VERSION 5.7 ;
BUSBITCHARS "[]" ;
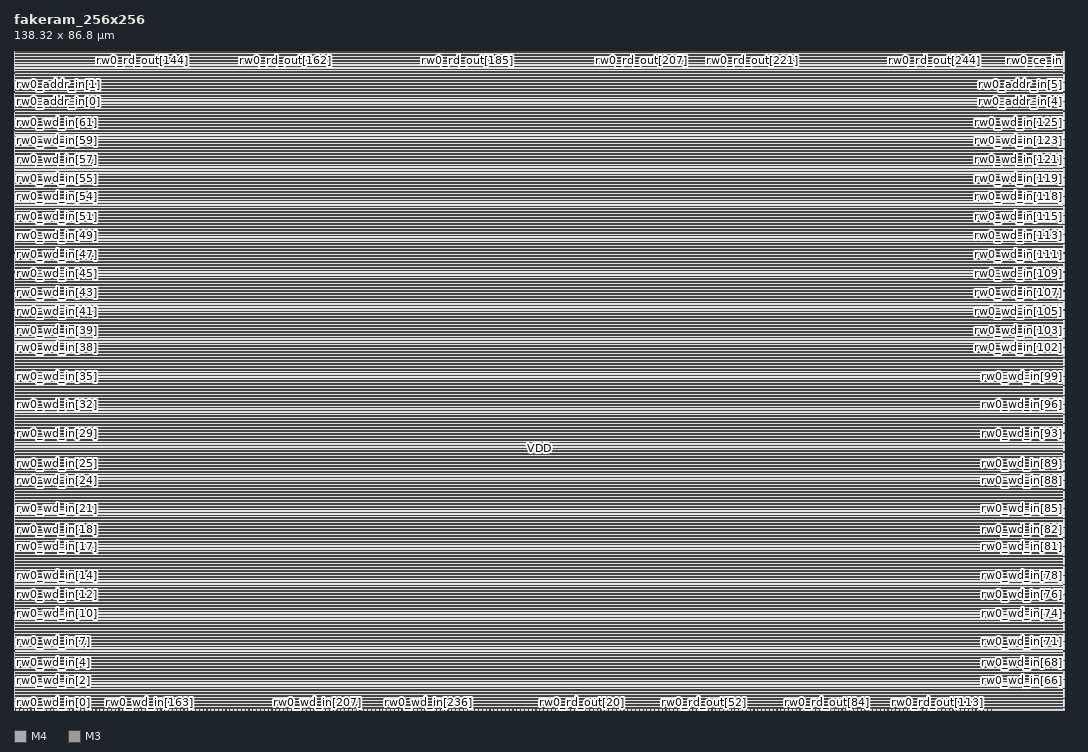
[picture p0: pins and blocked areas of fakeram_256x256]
MACRO fakeram_256x256
  FOREIGN fakeram_256x256 0 0 ;
  SYMMETRY X Y R90 ;
  SIZE 138.320 BY 86.800 ;
  CLASS BLOCK ;
  PIN rw0_wd_in[0]
    DIRECTION INPUT ;
    USE SIGNAL ;
    SHAPE ABUTMENT ;
    PORT
      LAYER M4 ;
      RECT 0.000 0.276 0.072 0.300 ;
    END
  END rw0_wd_in[0]
  PIN rw0_wd_in[1]
    DIRECTION INPUT ;
    USE SIGNAL ;
    SHAPE ABUTMENT ;
    PORT
      LAYER M4 ;
      RECT 0.000 1.524 0.072 1.548 ;
    END
  END rw0_wd_in[1]
  PIN rw0_wd_in[2]
    DIRECTION INPUT ;
    USE SIGNAL ;
    SHAPE ABUTMENT ;
    PORT
      LAYER M4 ;
      RECT 0.000 2.772 0.072 2.796 ;
    END
  END rw0_wd_in[2]
  PIN rw0_wd_in[3]
    DIRECTION INPUT ;
    USE SIGNAL ;
    SHAPE ABUTMENT ;
    PORT
      LAYER M4 ;
      RECT 0.000 4.020 0.072 4.044 ;
    END
  END rw0_wd_in[3]
  PIN rw0_wd_in[4]
    DIRECTION INPUT ;
    USE SIGNAL ;
    SHAPE ABUTMENT ;
    PORT
      LAYER M4 ;
      RECT 0.000 5.268 0.072 5.292 ;
    END
  END rw0_wd_in[4]
  PIN rw0_wd_in[5]
    DIRECTION INPUT ;
    USE SIGNAL ;
    SHAPE ABUTMENT ;
    PORT
      LAYER M4 ;
      RECT 0.000 6.516 0.072 6.540 ;
    END
  END rw0_wd_in[5]
  PIN rw0_wd_in[6]
    DIRECTION INPUT ;
    USE SIGNAL ;
    SHAPE ABUTMENT ;
    PORT
      LAYER M4 ;
      RECT 0.000 7.764 0.072 7.788 ;
    END
  END rw0_wd_in[6]
  PIN rw0_wd_in[7]
    DIRECTION INPUT ;
    USE SIGNAL ;
    SHAPE ABUTMENT ;
    PORT
      LAYER M4 ;
      RECT 0.000 9.012 0.072 9.036 ;
    END
  END rw0_wd_in[7]
  PIN rw0_wd_in[8]
    DIRECTION INPUT ;
    USE SIGNAL ;
    SHAPE ABUTMENT ;
    PORT
      LAYER M4 ;
      RECT 0.000 10.260 0.072 10.284 ;
    END
  END rw0_wd_in[8]
  PIN rw0_wd_in[9]
    DIRECTION INPUT ;
    USE SIGNAL ;
    SHAPE ABUTMENT ;
    PORT
      LAYER M4 ;
      RECT 0.000 11.508 0.072 11.532 ;
    END
  END rw0_wd_in[9]
  PIN rw0_wd_in[10]
    DIRECTION INPUT ;
    USE SIGNAL ;
    SHAPE ABUTMENT ;
    PORT
      LAYER M4 ;
      RECT 0.000 12.756 0.072 12.780 ;
    END
  END rw0_wd_in[10]
  PIN rw0_wd_in[11]
    DIRECTION INPUT ;
    USE SIGNAL ;
    SHAPE ABUTMENT ;
    PORT
      LAYER M4 ;
      RECT 0.000 14.004 0.072 14.028 ;
    END
  END rw0_wd_in[11]
  PIN rw0_wd_in[12]
    DIRECTION INPUT ;
    USE SIGNAL ;
    SHAPE ABUTMENT ;
    PORT
      LAYER M4 ;
      RECT 0.000 15.252 0.072 15.276 ;
    END
  END rw0_wd_in[12]
  PIN rw0_wd_in[13]
    DIRECTION INPUT ;
    USE SIGNAL ;
    SHAPE ABUTMENT ;
    PORT
      LAYER M4 ;
      RECT 0.000 16.500 0.072 16.524 ;
    END
  END rw0_wd_in[13]
  PIN rw0_wd_in[14]
    DIRECTION INPUT ;
    USE SIGNAL ;
    SHAPE ABUTMENT ;
    PORT
      LAYER M4 ;
      RECT 0.000 17.748 0.072 17.772 ;
    END
  END rw0_wd_in[14]
  PIN rw0_wd_in[15]
    DIRECTION INPUT ;
    USE SIGNAL ;
    SHAPE ABUTMENT ;
    PORT
      LAYER M4 ;
      RECT 0.000 18.996 0.072 19.020 ;
    END
  END rw0_wd_in[15]
  PIN rw0_wd_in[16]
    DIRECTION INPUT ;
    USE SIGNAL ;
    SHAPE ABUTMENT ;
    PORT
      LAYER M4 ;
      RECT 0.000 20.244 0.072 20.268 ;
    END
  END rw0_wd_in[16]
  PIN rw0_wd_in[17]
    DIRECTION INPUT ;
    USE SIGNAL ;
    SHAPE ABUTMENT ;
    PORT
      LAYER M4 ;
      RECT 0.000 21.492 0.072 21.516 ;
    END
  END rw0_wd_in[17]
  PIN rw0_wd_in[18]
    DIRECTION INPUT ;
    USE SIGNAL ;
    SHAPE ABUTMENT ;
    PORT
      LAYER M4 ;
      RECT 0.000 22.740 0.072 22.764 ;
    END
  END rw0_wd_in[18]
  PIN rw0_wd_in[19]
    DIRECTION INPUT ;
    USE SIGNAL ;
    SHAPE ABUTMENT ;
    PORT
      LAYER M4 ;
      RECT 0.000 23.988 0.072 24.012 ;
    END
  END rw0_wd_in[19]
  PIN rw0_wd_in[20]
    DIRECTION INPUT ;
    USE SIGNAL ;
    SHAPE ABUTMENT ;
    PORT
      LAYER M4 ;
      RECT 0.000 25.236 0.072 25.260 ;
    END
  END rw0_wd_in[20]
  PIN rw0_wd_in[21]
    DIRECTION INPUT ;
    USE SIGNAL ;
    SHAPE ABUTMENT ;
    PORT
      LAYER M4 ;
      RECT 0.000 26.484 0.072 26.508 ;
    END
  END rw0_wd_in[21]
  PIN rw0_wd_in[22]
    DIRECTION INPUT ;
    USE SIGNAL ;
    SHAPE ABUTMENT ;
    PORT
      LAYER M4 ;
      RECT 0.000 27.732 0.072 27.756 ;
    END
  END rw0_wd_in[22]
  PIN rw0_wd_in[23]
    DIRECTION INPUT ;
    USE SIGNAL ;
    SHAPE ABUTMENT ;
    PORT
      LAYER M4 ;
      RECT 0.000 28.980 0.072 29.004 ;
    END
  END rw0_wd_in[23]
  PIN rw0_wd_in[24]
    DIRECTION INPUT ;
    USE SIGNAL ;
    SHAPE ABUTMENT ;
    PORT
      LAYER M4 ;
      RECT 0.000 30.228 0.072 30.252 ;
    END
  END rw0_wd_in[24]
  PIN rw0_wd_in[25]
    DIRECTION INPUT ;
    USE SIGNAL ;
    SHAPE ABUTMENT ;
    PORT
      LAYER M4 ;
      RECT 0.000 31.476 0.072 31.500 ;
    END
  END rw0_wd_in[25]
  PIN rw0_wd_in[26]
    DIRECTION INPUT ;
    USE SIGNAL ;
    SHAPE ABUTMENT ;
    PORT
      LAYER M4 ;
      RECT 0.000 32.724 0.072 32.748 ;
    END
  END rw0_wd_in[26]
  PIN rw0_wd_in[27]
    DIRECTION INPUT ;
    USE SIGNAL ;
    SHAPE ABUTMENT ;
    PORT
      LAYER M4 ;
      RECT 0.000 33.972 0.072 33.996 ;
    END
  END rw0_wd_in[27]
  PIN rw0_wd_in[28]
    DIRECTION INPUT ;
    USE SIGNAL ;
    SHAPE ABUTMENT ;
    PORT
      LAYER M4 ;
      RECT 0.000 35.220 0.072 35.244 ;
    END
  END rw0_wd_in[28]
  PIN rw0_wd_in[29]
    DIRECTION INPUT ;
    USE SIGNAL ;
    SHAPE ABUTMENT ;
    PORT
      LAYER M4 ;
      RECT 0.000 36.468 0.072 36.492 ;
    END
  END rw0_wd_in[29]
  PIN rw0_wd_in[30]
    DIRECTION INPUT ;
    USE SIGNAL ;
    SHAPE ABUTMENT ;
    PORT
      LAYER M4 ;
      RECT 0.000 37.716 0.072 37.740 ;
    END
  END rw0_wd_in[30]
  PIN rw0_wd_in[31]
    DIRECTION INPUT ;
    USE SIGNAL ;
    SHAPE ABUTMENT ;
    PORT
      LAYER M4 ;
      RECT 0.000 38.964 0.072 38.988 ;
    END
  END rw0_wd_in[31]
  PIN rw0_wd_in[32]
    DIRECTION INPUT ;
    USE SIGNAL ;
    SHAPE ABUTMENT ;
    PORT
      LAYER M4 ;
      RECT 0.000 40.212 0.072 40.236 ;
    END
  END rw0_wd_in[32]
  PIN rw0_wd_in[33]
    DIRECTION INPUT ;
    USE SIGNAL ;
    SHAPE ABUTMENT ;
    PORT
      LAYER M4 ;
      RECT 0.000 41.460 0.072 41.484 ;
    END
  END rw0_wd_in[33]
  PIN rw0_wd_in[34]
    DIRECTION INPUT ;
    USE SIGNAL ;
    SHAPE ABUTMENT ;
    PORT
      LAYER M4 ;
      RECT 0.000 42.708 0.072 42.732 ;
    END
  END rw0_wd_in[34]
  PIN rw0_wd_in[35]
    DIRECTION INPUT ;
    USE SIGNAL ;
    SHAPE ABUTMENT ;
    PORT
      LAYER M4 ;
      RECT 0.000 43.956 0.072 43.980 ;
    END
  END rw0_wd_in[35]
  PIN rw0_wd_in[36]
    DIRECTION INPUT ;
    USE SIGNAL ;
    SHAPE ABUTMENT ;
    PORT
      LAYER M4 ;
      RECT 0.000 45.204 0.072 45.228 ;
    END
  END rw0_wd_in[36]
  PIN rw0_wd_in[37]
    DIRECTION INPUT ;
    USE SIGNAL ;
    SHAPE ABUTMENT ;
    PORT
      LAYER M4 ;
      RECT 0.000 46.452 0.072 46.476 ;
    END
  END rw0_wd_in[37]
  PIN rw0_wd_in[38]
    DIRECTION INPUT ;
    USE SIGNAL ;
    SHAPE ABUTMENT ;
    PORT
      LAYER M4 ;
      RECT 0.000 47.700 0.072 47.724 ;
    END
  END rw0_wd_in[38]
  PIN rw0_wd_in[39]
    DIRECTION INPUT ;
    USE SIGNAL ;
    SHAPE ABUTMENT ;
    PORT
      LAYER M4 ;
      RECT 0.000 48.948 0.072 48.972 ;
    END
  END rw0_wd_in[39]
  PIN rw0_wd_in[40]
    DIRECTION INPUT ;
    USE SIGNAL ;
    SHAPE ABUTMENT ;
    PORT
      LAYER M4 ;
      RECT 0.000 50.196 0.072 50.220 ;
    END
  END rw0_wd_in[40]
  PIN rw0_wd_in[41]
    DIRECTION INPUT ;
    USE SIGNAL ;
    SHAPE ABUTMENT ;
    PORT
      LAYER M4 ;
      RECT 0.000 51.444 0.072 51.468 ;
    END
  END rw0_wd_in[41]
  PIN rw0_wd_in[42]
    DIRECTION INPUT ;
    USE SIGNAL ;
    SHAPE ABUTMENT ;
    PORT
      LAYER M4 ;
      RECT 0.000 52.692 0.072 52.716 ;
    END
  END rw0_wd_in[42]
  PIN rw0_wd_in[43]
    DIRECTION INPUT ;
    USE SIGNAL ;
    SHAPE ABUTMENT ;
    PORT
      LAYER M4 ;
      RECT 0.000 53.940 0.072 53.964 ;
    END
  END rw0_wd_in[43]
  PIN rw0_wd_in[44]
    DIRECTION INPUT ;
    USE SIGNAL ;
    SHAPE ABUTMENT ;
    PORT
      LAYER M4 ;
      RECT 0.000 55.188 0.072 55.212 ;
    END
  END rw0_wd_in[44]
  PIN rw0_wd_in[45]
    DIRECTION INPUT ;
    USE SIGNAL ;
    SHAPE ABUTMENT ;
    PORT
      LAYER M4 ;
      RECT 0.000 56.436 0.072 56.460 ;
    END
  END rw0_wd_in[45]
  PIN rw0_wd_in[46]
    DIRECTION INPUT ;
    USE SIGNAL ;
    SHAPE ABUTMENT ;
    PORT
      LAYER M4 ;
      RECT 0.000 57.684 0.072 57.708 ;
    END
  END rw0_wd_in[46]
  PIN rw0_wd_in[47]
    DIRECTION INPUT ;
    USE SIGNAL ;
    SHAPE ABUTMENT ;
    PORT
      LAYER M4 ;
      RECT 0.000 58.932 0.072 58.956 ;
    END
  END rw0_wd_in[47]
  PIN rw0_wd_in[48]
    DIRECTION INPUT ;
    USE SIGNAL ;
    SHAPE ABUTMENT ;
    PORT
      LAYER M4 ;
      RECT 0.000 60.180 0.072 60.204 ;
    END
  END rw0_wd_in[48]
  PIN rw0_wd_in[49]
    DIRECTION INPUT ;
    USE SIGNAL ;
    SHAPE ABUTMENT ;
    PORT
      LAYER M4 ;
      RECT 0.000 61.428 0.072 61.452 ;
    END
  END rw0_wd_in[49]
  PIN rw0_wd_in[50]
    DIRECTION INPUT ;
    USE SIGNAL ;
    SHAPE ABUTMENT ;
    PORT
      LAYER M4 ;
      RECT 0.000 62.676 0.072 62.700 ;
    END
  END rw0_wd_in[50]
  PIN rw0_wd_in[51]
    DIRECTION INPUT ;
    USE SIGNAL ;
    SHAPE ABUTMENT ;
    PORT
      LAYER M4 ;
      RECT 0.000 63.924 0.072 63.948 ;
    END
  END rw0_wd_in[51]
  PIN rw0_wd_in[52]
    DIRECTION INPUT ;
    USE SIGNAL ;
    SHAPE ABUTMENT ;
    PORT
      LAYER M4 ;
      RECT 0.000 65.172 0.072 65.196 ;
    END
  END rw0_wd_in[52]
  PIN rw0_wd_in[53]
    DIRECTION INPUT ;
    USE SIGNAL ;
    SHAPE ABUTMENT ;
    PORT
      LAYER M4 ;
      RECT 0.000 66.420 0.072 66.444 ;
    END
  END rw0_wd_in[53]
  PIN rw0_wd_in[54]
    DIRECTION INPUT ;
    USE SIGNAL ;
    SHAPE ABUTMENT ;
    PORT
      LAYER M4 ;
      RECT 0.000 67.668 0.072 67.692 ;
    END
  END rw0_wd_in[54]
  PIN rw0_wd_in[55]
    DIRECTION INPUT ;
    USE SIGNAL ;
    SHAPE ABUTMENT ;
    PORT
      LAYER M4 ;
      RECT 0.000 68.916 0.072 68.940 ;
    END
  END rw0_wd_in[55]
  PIN rw0_wd_in[56]
    DIRECTION INPUT ;
    USE SIGNAL ;
    SHAPE ABUTMENT ;
    PORT
      LAYER M4 ;
      RECT 0.000 70.164 0.072 70.188 ;
    END
  END rw0_wd_in[56]
  PIN rw0_wd_in[57]
    DIRECTION INPUT ;
    USE SIGNAL ;
    SHAPE ABUTMENT ;
    PORT
      LAYER M4 ;
      RECT 0.000 71.412 0.072 71.436 ;
    END
  END rw0_wd_in[57]
  PIN rw0_wd_in[58]
    DIRECTION INPUT ;
    USE SIGNAL ;
    SHAPE ABUTMENT ;
    PORT
      LAYER M4 ;
      RECT 0.000 72.660 0.072 72.684 ;
    END
  END rw0_wd_in[58]
  PIN rw0_wd_in[59]
    DIRECTION INPUT ;
    USE SIGNAL ;
    SHAPE ABUTMENT ;
    PORT
      LAYER M4 ;
      RECT 0.000 73.908 0.072 73.932 ;
    END
  END rw0_wd_in[59]
  PIN rw0_wd_in[60]
    DIRECTION INPUT ;
    USE SIGNAL ;
    SHAPE ABUTMENT ;
    PORT
      LAYER M4 ;
      RECT 0.000 75.156 0.072 75.180 ;
    END
  END rw0_wd_in[60]
  PIN rw0_wd_in[61]
    DIRECTION INPUT ;
    USE SIGNAL ;
    SHAPE ABUTMENT ;
    PORT
      LAYER M4 ;
      RECT 0.000 76.404 0.072 76.428 ;
    END
  END rw0_wd_in[61]
  PIN rw0_wd_in[62]
    DIRECTION INPUT ;
    USE SIGNAL ;
    SHAPE ABUTMENT ;
    PORT
      LAYER M4 ;
      RECT 0.000 77.652 0.072 77.676 ;
    END
  END rw0_wd_in[62]
  PIN rw0_wd_in[63]
    DIRECTION INPUT ;
    USE SIGNAL ;
    SHAPE ABUTMENT ;
    PORT
      LAYER M4 ;
      RECT 0.000 78.900 0.072 78.924 ;
    END
  END rw0_wd_in[63]
  PIN rw0_wd_in[64]
    DIRECTION INPUT ;
    USE SIGNAL ;
    SHAPE ABUTMENT ;
    PORT
      LAYER M4 ;
      RECT 138.248 0.276 138.320 0.300 ;
    END
  END rw0_wd_in[64]
  PIN rw0_wd_in[65]
    DIRECTION INPUT ;
    USE SIGNAL ;
    SHAPE ABUTMENT ;
    PORT
      LAYER M4 ;
      RECT 138.248 1.524 138.320 1.548 ;
    END
  END rw0_wd_in[65]
  PIN rw0_wd_in[66]
    DIRECTION INPUT ;
    USE SIGNAL ;
    SHAPE ABUTMENT ;
    PORT
      LAYER M4 ;
      RECT 138.248 2.772 138.320 2.796 ;
    END
  END rw0_wd_in[66]
  PIN rw0_wd_in[67]
    DIRECTION INPUT ;
    USE SIGNAL ;
    SHAPE ABUTMENT ;
    PORT
      LAYER M4 ;
      RECT 138.248 4.020 138.320 4.044 ;
    END
  END rw0_wd_in[67]
  PIN rw0_wd_in[68]
    DIRECTION INPUT ;
    USE SIGNAL ;
    SHAPE ABUTMENT ;
    PORT
      LAYER M4 ;
      RECT 138.248 5.268 138.320 5.292 ;
    END
  END rw0_wd_in[68]
  PIN rw0_wd_in[69]
    DIRECTION INPUT ;
    USE SIGNAL ;
    SHAPE ABUTMENT ;
    PORT
      LAYER M4 ;
      RECT 138.248 6.516 138.320 6.540 ;
    END
  END rw0_wd_in[69]
  PIN rw0_wd_in[70]
    DIRECTION INPUT ;
    USE SIGNAL ;
    SHAPE ABUTMENT ;
    PORT
      LAYER M4 ;
      RECT 138.248 7.764 138.320 7.788 ;
    END
  END rw0_wd_in[70]
  PIN rw0_wd_in[71]
    DIRECTION INPUT ;
    USE SIGNAL ;
    SHAPE ABUTMENT ;
    PORT
      LAYER M4 ;
      RECT 138.248 9.012 138.320 9.036 ;
    END
  END rw0_wd_in[71]
  PIN rw0_wd_in[72]
    DIRECTION INPUT ;
    USE SIGNAL ;
    SHAPE ABUTMENT ;
    PORT
      LAYER M4 ;
      RECT 138.248 10.260 138.320 10.284 ;
    END
  END rw0_wd_in[72]
  PIN rw0_wd_in[73]
    DIRECTION INPUT ;
    USE SIGNAL ;
    SHAPE ABUTMENT ;
    PORT
      LAYER M4 ;
      RECT 138.248 11.508 138.320 11.532 ;
    END
  END rw0_wd_in[73]
  PIN rw0_wd_in[74]
    DIRECTION INPUT ;
    USE SIGNAL ;
    SHAPE ABUTMENT ;
    PORT
      LAYER M4 ;
      RECT 138.248 12.756 138.320 12.780 ;
    END
  END rw0_wd_in[74]
  PIN rw0_wd_in[75]
    DIRECTION INPUT ;
    USE SIGNAL ;
    SHAPE ABUTMENT ;
    PORT
      LAYER M4 ;
      RECT 138.248 14.004 138.320 14.028 ;
    END
  END rw0_wd_in[75]
  PIN rw0_wd_in[76]
    DIRECTION INPUT ;
    USE SIGNAL ;
    SHAPE ABUTMENT ;
    PORT
      LAYER M4 ;
      RECT 138.248 15.252 138.320 15.276 ;
    END
  END rw0_wd_in[76]
  PIN rw0_wd_in[77]
    DIRECTION INPUT ;
    USE SIGNAL ;
    SHAPE ABUTMENT ;
    PORT
      LAYER M4 ;
      RECT 138.248 16.500 138.320 16.524 ;
    END
  END rw0_wd_in[77]
  PIN rw0_wd_in[78]
    DIRECTION INPUT ;
    USE SIGNAL ;
    SHAPE ABUTMENT ;
    PORT
      LAYER M4 ;
      RECT 138.248 17.748 138.320 17.772 ;
    END
  END rw0_wd_in[78]
  PIN rw0_wd_in[79]
    DIRECTION INPUT ;
    USE SIGNAL ;
    SHAPE ABUTMENT ;
    PORT
      LAYER M4 ;
      RECT 138.248 18.996 138.320 19.020 ;
    END
  END rw0_wd_in[79]
  PIN rw0_wd_in[80]
    DIRECTION INPUT ;
    USE SIGNAL ;
    SHAPE ABUTMENT ;
    PORT
      LAYER M4 ;
      RECT 138.248 20.244 138.320 20.268 ;
    END
  END rw0_wd_in[80]
  PIN rw0_wd_in[81]
    DIRECTION INPUT ;
    USE SIGNAL ;
    SHAPE ABUTMENT ;
    PORT
      LAYER M4 ;
      RECT 138.248 21.492 138.320 21.516 ;
    END
  END rw0_wd_in[81]
  PIN rw0_wd_in[82]
    DIRECTION INPUT ;
    USE SIGNAL ;
    SHAPE ABUTMENT ;
    PORT
      LAYER M4 ;
      RECT 138.248 22.740 138.320 22.764 ;
    END
  END rw0_wd_in[82]
  PIN rw0_wd_in[83]
    DIRECTION INPUT ;
    USE SIGNAL ;
    SHAPE ABUTMENT ;
    PORT
      LAYER M4 ;
      RECT 138.248 23.988 138.320 24.012 ;
    END
  END rw0_wd_in[83]
  PIN rw0_wd_in[84]
    DIRECTION INPUT ;
    USE SIGNAL ;
    SHAPE ABUTMENT ;
    PORT
      LAYER M4 ;
      RECT 138.248 25.236 138.320 25.260 ;
    END
  END rw0_wd_in[84]
  PIN rw0_wd_in[85]
    DIRECTION INPUT ;
    USE SIGNAL ;
    SHAPE ABUTMENT ;
    PORT
      LAYER M4 ;
      RECT 138.248 26.484 138.320 26.508 ;
    END
  END rw0_wd_in[85]
  PIN rw0_wd_in[86]
    DIRECTION INPUT ;
    USE SIGNAL ;
    SHAPE ABUTMENT ;
    PORT
      LAYER M4 ;
      RECT 138.248 27.732 138.320 27.756 ;
    END
  END rw0_wd_in[86]
  PIN rw0_wd_in[87]
    DIRECTION INPUT ;
    USE SIGNAL ;
    SHAPE ABUTMENT ;
    PORT
      LAYER M4 ;
      RECT 138.248 28.980 138.320 29.004 ;
    END
  END rw0_wd_in[87]
  PIN rw0_wd_in[88]
    DIRECTION INPUT ;
    USE SIGNAL ;
    SHAPE ABUTMENT ;
    PORT
      LAYER M4 ;
      RECT 138.248 30.228 138.320 30.252 ;
    END
  END rw0_wd_in[88]
  PIN rw0_wd_in[89]
    DIRECTION INPUT ;
    USE SIGNAL ;
    SHAPE ABUTMENT ;
    PORT
      LAYER M4 ;
      RECT 138.248 31.476 138.320 31.500 ;
    END
  END rw0_wd_in[89]
  PIN rw0_wd_in[90]
    DIRECTION INPUT ;
    USE SIGNAL ;
    SHAPE ABUTMENT ;
    PORT
      LAYER M4 ;
      RECT 138.248 32.724 138.320 32.748 ;
    END
  END rw0_wd_in[90]
  PIN rw0_wd_in[91]
    DIRECTION INPUT ;
    USE SIGNAL ;
    SHAPE ABUTMENT ;
    PORT
      LAYER M4 ;
      RECT 138.248 33.972 138.320 33.996 ;
    END
  END rw0_wd_in[91]
  PIN rw0_wd_in[92]
    DIRECTION INPUT ;
    USE SIGNAL ;
    SHAPE ABUTMENT ;
    PORT
      LAYER M4 ;
      RECT 138.248 35.220 138.320 35.244 ;
    END
  END rw0_wd_in[92]
  PIN rw0_wd_in[93]
    DIRECTION INPUT ;
    USE SIGNAL ;
    SHAPE ABUTMENT ;
    PORT
      LAYER M4 ;
      RECT 138.248 36.468 138.320 36.492 ;
    END
  END rw0_wd_in[93]
  PIN rw0_wd_in[94]
    DIRECTION INPUT ;
    USE SIGNAL ;
    SHAPE ABUTMENT ;
    PORT
      LAYER M4 ;
      RECT 138.248 37.716 138.320 37.740 ;
    END
  END rw0_wd_in[94]
  PIN rw0_wd_in[95]
    DIRECTION INPUT ;
    USE SIGNAL ;
    SHAPE ABUTMENT ;
    PORT
      LAYER M4 ;
      RECT 138.248 38.964 138.320 38.988 ;
    END
  END rw0_wd_in[95]
  PIN rw0_wd_in[96]
    DIRECTION INPUT ;
    USE SIGNAL ;
    SHAPE ABUTMENT ;
    PORT
      LAYER M4 ;
      RECT 138.248 40.212 138.320 40.236 ;
    END
  END rw0_wd_in[96]
  PIN rw0_wd_in[97]
    DIRECTION INPUT ;
    USE SIGNAL ;
    SHAPE ABUTMENT ;
    PORT
      LAYER M4 ;
      RECT 138.248 41.460 138.320 41.484 ;
    END
  END rw0_wd_in[97]
  PIN rw0_wd_in[98]
    DIRECTION INPUT ;
    USE SIGNAL ;
    SHAPE ABUTMENT ;
    PORT
      LAYER M4 ;
      RECT 138.248 42.708 138.320 42.732 ;
    END
  END rw0_wd_in[98]
  PIN rw0_wd_in[99]
    DIRECTION INPUT ;
    USE SIGNAL ;
    SHAPE ABUTMENT ;
    PORT
      LAYER M4 ;
      RECT 138.248 43.956 138.320 43.980 ;
    END
  END rw0_wd_in[99]
  PIN rw0_wd_in[100]
    DIRECTION INPUT ;
    USE SIGNAL ;
    SHAPE ABUTMENT ;
    PORT
      LAYER M4 ;
      RECT 138.248 45.204 138.320 45.228 ;
    END
  END rw0_wd_in[100]
  PIN rw0_wd_in[101]
    DIRECTION INPUT ;
    USE SIGNAL ;
    SHAPE ABUTMENT ;
    PORT
      LAYER M4 ;
      RECT 138.248 46.452 138.320 46.476 ;
    END
  END rw0_wd_in[101]
  PIN rw0_wd_in[102]
    DIRECTION INPUT ;
    USE SIGNAL ;
    SHAPE ABUTMENT ;
    PORT
      LAYER M4 ;
      RECT 138.248 47.700 138.320 47.724 ;
    END
  END rw0_wd_in[102]
  PIN rw0_wd_in[103]
    DIRECTION INPUT ;
    USE SIGNAL ;
    SHAPE ABUTMENT ;
    PORT
      LAYER M4 ;
      RECT 138.248 48.948 138.320 48.972 ;
    END
  END rw0_wd_in[103]
  PIN rw0_wd_in[104]
    DIRECTION INPUT ;
    USE SIGNAL ;
    SHAPE ABUTMENT ;
    PORT
      LAYER M4 ;
      RECT 138.248 50.196 138.320 50.220 ;
    END
  END rw0_wd_in[104]
  PIN rw0_wd_in[105]
    DIRECTION INPUT ;
    USE SIGNAL ;
    SHAPE ABUTMENT ;
    PORT
      LAYER M4 ;
      RECT 138.248 51.444 138.320 51.468 ;
    END
  END rw0_wd_in[105]
  PIN rw0_wd_in[106]
    DIRECTION INPUT ;
    USE SIGNAL ;
    SHAPE ABUTMENT ;
    PORT
      LAYER M4 ;
      RECT 138.248 52.692 138.320 52.716 ;
    END
  END rw0_wd_in[106]
  PIN rw0_wd_in[107]
    DIRECTION INPUT ;
    USE SIGNAL ;
    SHAPE ABUTMENT ;
    PORT
      LAYER M4 ;
      RECT 138.248 53.940 138.320 53.964 ;
    END
  END rw0_wd_in[107]
  PIN rw0_wd_in[108]
    DIRECTION INPUT ;
    USE SIGNAL ;
    SHAPE ABUTMENT ;
    PORT
      LAYER M4 ;
      RECT 138.248 55.188 138.320 55.212 ;
    END
  END rw0_wd_in[108]
  PIN rw0_wd_in[109]
    DIRECTION INPUT ;
    USE SIGNAL ;
    SHAPE ABUTMENT ;
    PORT
      LAYER M4 ;
      RECT 138.248 56.436 138.320 56.460 ;
    END
  END rw0_wd_in[109]
  PIN rw0_wd_in[110]
    DIRECTION INPUT ;
    USE SIGNAL ;
    SHAPE ABUTMENT ;
    PORT
      LAYER M4 ;
      RECT 138.248 57.684 138.320 57.708 ;
    END
  END rw0_wd_in[110]
  PIN rw0_wd_in[111]
    DIRECTION INPUT ;
    USE SIGNAL ;
    SHAPE ABUTMENT ;
    PORT
      LAYER M4 ;
      RECT 138.248 58.932 138.320 58.956 ;
    END
  END rw0_wd_in[111]
  PIN rw0_wd_in[112]
    DIRECTION INPUT ;
    USE SIGNAL ;
    SHAPE ABUTMENT ;
    PORT
      LAYER M4 ;
      RECT 138.248 60.180 138.320 60.204 ;
    END
  END rw0_wd_in[112]
  PIN rw0_wd_in[113]
    DIRECTION INPUT ;
    USE SIGNAL ;
    SHAPE ABUTMENT ;
    PORT
      LAYER M4 ;
      RECT 138.248 61.428 138.320 61.452 ;
    END
  END rw0_wd_in[113]
  PIN rw0_wd_in[114]
    DIRECTION INPUT ;
    USE SIGNAL ;
    SHAPE ABUTMENT ;
    PORT
      LAYER M4 ;
      RECT 138.248 62.676 138.320 62.700 ;
    END
  END rw0_wd_in[114]
  PIN rw0_wd_in[115]
    DIRECTION INPUT ;
    USE SIGNAL ;
    SHAPE ABUTMENT ;
    PORT
      LAYER M4 ;
      RECT 138.248 63.924 138.320 63.948 ;
    END
  END rw0_wd_in[115]
  PIN rw0_wd_in[116]
    DIRECTION INPUT ;
    USE SIGNAL ;
    SHAPE ABUTMENT ;
    PORT
      LAYER M4 ;
      RECT 138.248 65.172 138.320 65.196 ;
    END
  END rw0_wd_in[116]
  PIN rw0_wd_in[117]
    DIRECTION INPUT ;
    USE SIGNAL ;
    SHAPE ABUTMENT ;
    PORT
      LAYER M4 ;
      RECT 138.248 66.420 138.320 66.444 ;
    END
  END rw0_wd_in[117]
  PIN rw0_wd_in[118]
    DIRECTION INPUT ;
    USE SIGNAL ;
    SHAPE ABUTMENT ;
    PORT
      LAYER M4 ;
      RECT 138.248 67.668 138.320 67.692 ;
    END
  END rw0_wd_in[118]
  PIN rw0_wd_in[119]
    DIRECTION INPUT ;
    USE SIGNAL ;
    SHAPE ABUTMENT ;
    PORT
      LAYER M4 ;
      RECT 138.248 68.916 138.320 68.940 ;
    END
  END rw0_wd_in[119]
  PIN rw0_wd_in[120]
    DIRECTION INPUT ;
    USE SIGNAL ;
    SHAPE ABUTMENT ;
    PORT
      LAYER M4 ;
      RECT 138.248 70.164 138.320 70.188 ;
    END
  END rw0_wd_in[120]
  PIN rw0_wd_in[121]
    DIRECTION INPUT ;
    USE SIGNAL ;
    SHAPE ABUTMENT ;
    PORT
      LAYER M4 ;
      RECT 138.248 71.412 138.320 71.436 ;
    END
  END rw0_wd_in[121]
  PIN rw0_wd_in[122]
    DIRECTION INPUT ;
    USE SIGNAL ;
    SHAPE ABUTMENT ;
    PORT
      LAYER M4 ;
      RECT 138.248 72.660 138.320 72.684 ;
    END
  END rw0_wd_in[122]
  PIN rw0_wd_in[123]
    DIRECTION INPUT ;
    USE SIGNAL ;
    SHAPE ABUTMENT ;
    PORT
      LAYER M4 ;
      RECT 138.248 73.908 138.320 73.932 ;
    END
  END rw0_wd_in[123]
  PIN rw0_wd_in[124]
    DIRECTION INPUT ;
    USE SIGNAL ;
    SHAPE ABUTMENT ;
    PORT
      LAYER M4 ;
      RECT 138.248 75.156 138.320 75.180 ;
    END
  END rw0_wd_in[124]
  PIN rw0_wd_in[125]
    DIRECTION INPUT ;
    USE SIGNAL ;
    SHAPE ABUTMENT ;
    PORT
      LAYER M4 ;
      RECT 138.248 76.404 138.320 76.428 ;
    END
  END rw0_wd_in[125]
  PIN rw0_wd_in[126]
    DIRECTION INPUT ;
    USE SIGNAL ;
    SHAPE ABUTMENT ;
    PORT
      LAYER M4 ;
      RECT 138.248 77.652 138.320 77.676 ;
    END
  END rw0_wd_in[126]
  PIN rw0_wd_in[127]
    DIRECTION INPUT ;
    USE SIGNAL ;
    SHAPE ABUTMENT ;
    PORT
      LAYER M4 ;
      RECT 138.248 78.900 138.320 78.924 ;
    END
  END rw0_wd_in[127]
  PIN rw0_wd_in[128]
    DIRECTION INPUT ;
    USE SIGNAL ;
    SHAPE ABUTMENT ;
    PORT
      LAYER M3 ;
      RECT 0.207 0.000 0.225 0.054 ;
    END
  END rw0_wd_in[128]
  PIN rw0_wd_in[129]
    DIRECTION INPUT ;
    USE SIGNAL ;
    SHAPE ABUTMENT ;
    PORT
      LAYER M3 ;
      RECT 0.711 0.000 0.729 0.054 ;
    END
  END rw0_wd_in[129]
  PIN rw0_wd_in[130]
    DIRECTION INPUT ;
    USE SIGNAL ;
    SHAPE ABUTMENT ;
    PORT
      LAYER M3 ;
      RECT 1.215 0.000 1.233 0.054 ;
    END
  END rw0_wd_in[130]
  PIN rw0_wd_in[131]
    DIRECTION INPUT ;
    USE SIGNAL ;
    SHAPE ABUTMENT ;
    PORT
      LAYER M3 ;
      RECT 1.719 0.000 1.737 0.054 ;
    END
  END rw0_wd_in[131]
  PIN rw0_wd_in[132]
    DIRECTION INPUT ;
    USE SIGNAL ;
    SHAPE ABUTMENT ;
    PORT
      LAYER M3 ;
      RECT 2.223 0.000 2.241 0.054 ;
    END
  END rw0_wd_in[132]
  PIN rw0_wd_in[133]
    DIRECTION INPUT ;
    USE SIGNAL ;
    SHAPE ABUTMENT ;
    PORT
      LAYER M3 ;
      RECT 2.727 0.000 2.745 0.054 ;
    END
  END rw0_wd_in[133]
  PIN rw0_wd_in[134]
    DIRECTION INPUT ;
    USE SIGNAL ;
    SHAPE ABUTMENT ;
    PORT
      LAYER M3 ;
      RECT 3.231 0.000 3.249 0.054 ;
    END
  END rw0_wd_in[134]
  PIN rw0_wd_in[135]
    DIRECTION INPUT ;
    USE SIGNAL ;
    SHAPE ABUTMENT ;
    PORT
      LAYER M3 ;
      RECT 3.735 0.000 3.753 0.054 ;
    END
  END rw0_wd_in[135]
  PIN rw0_wd_in[136]
    DIRECTION INPUT ;
    USE SIGNAL ;
    SHAPE ABUTMENT ;
    PORT
      LAYER M3 ;
      RECT 4.239 0.000 4.257 0.054 ;
    END
  END rw0_wd_in[136]
  PIN rw0_wd_in[137]
    DIRECTION INPUT ;
    USE SIGNAL ;
    SHAPE ABUTMENT ;
    PORT
      LAYER M3 ;
      RECT 4.743 0.000 4.761 0.054 ;
    END
  END rw0_wd_in[137]
  PIN rw0_wd_in[138]
    DIRECTION INPUT ;
    USE SIGNAL ;
    SHAPE ABUTMENT ;
    PORT
      LAYER M3 ;
      RECT 5.247 0.000 5.265 0.054 ;
    END
  END rw0_wd_in[138]
  PIN rw0_wd_in[139]
    DIRECTION INPUT ;
    USE SIGNAL ;
    SHAPE ABUTMENT ;
    PORT
      LAYER M3 ;
      RECT 5.751 0.000 5.769 0.054 ;
    END
  END rw0_wd_in[139]
  PIN rw0_wd_in[140]
    DIRECTION INPUT ;
    USE SIGNAL ;
    SHAPE ABUTMENT ;
    PORT
      LAYER M3 ;
      RECT 6.255 0.000 6.273 0.054 ;
    END
  END rw0_wd_in[140]
  PIN rw0_wd_in[141]
    DIRECTION INPUT ;
    USE SIGNAL ;
    SHAPE ABUTMENT ;
    PORT
      LAYER M3 ;
      RECT 6.759 0.000 6.777 0.054 ;
    END
  END rw0_wd_in[141]
  PIN rw0_wd_in[142]
    DIRECTION INPUT ;
    USE SIGNAL ;
    SHAPE ABUTMENT ;
    PORT
      LAYER M3 ;
      RECT 7.263 0.000 7.281 0.054 ;
    END
  END rw0_wd_in[142]
  PIN rw0_wd_in[143]
    DIRECTION INPUT ;
    USE SIGNAL ;
    SHAPE ABUTMENT ;
    PORT
      LAYER M3 ;
      RECT 7.767 0.000 7.785 0.054 ;
    END
  END rw0_wd_in[143]
  PIN rw0_wd_in[144]
    DIRECTION INPUT ;
    USE SIGNAL ;
    SHAPE ABUTMENT ;
    PORT
      LAYER M3 ;
      RECT 8.271 0.000 8.289 0.054 ;
    END
  END rw0_wd_in[144]
  PIN rw0_wd_in[145]
    DIRECTION INPUT ;
    USE SIGNAL ;
    SHAPE ABUTMENT ;
    PORT
      LAYER M3 ;
      RECT 8.775 0.000 8.793 0.054 ;
    END
  END rw0_wd_in[145]
  PIN rw0_wd_in[146]
    DIRECTION INPUT ;
    USE SIGNAL ;
    SHAPE ABUTMENT ;
    PORT
      LAYER M3 ;
      RECT 9.279 0.000 9.297 0.054 ;
    END
  END rw0_wd_in[146]
  PIN rw0_wd_in[147]
    DIRECTION INPUT ;
    USE SIGNAL ;
    SHAPE ABUTMENT ;
    PORT
      LAYER M3 ;
      RECT 9.783 0.000 9.801 0.054 ;
    END
  END rw0_wd_in[147]
  PIN rw0_wd_in[148]
    DIRECTION INPUT ;
    USE SIGNAL ;
    SHAPE ABUTMENT ;
    PORT
      LAYER M3 ;
      RECT 10.287 0.000 10.305 0.054 ;
    END
  END rw0_wd_in[148]
  PIN rw0_wd_in[149]
    DIRECTION INPUT ;
    USE SIGNAL ;
    SHAPE ABUTMENT ;
    PORT
      LAYER M3 ;
      RECT 10.791 0.000 10.809 0.054 ;
    END
  END rw0_wd_in[149]
  PIN rw0_wd_in[150]
    DIRECTION INPUT ;
    USE SIGNAL ;
    SHAPE ABUTMENT ;
    PORT
      LAYER M3 ;
      RECT 11.295 0.000 11.313 0.054 ;
    END
  END rw0_wd_in[150]
  PIN rw0_wd_in[151]
    DIRECTION INPUT ;
    USE SIGNAL ;
    SHAPE ABUTMENT ;
    PORT
      LAYER M3 ;
      RECT 11.799 0.000 11.817 0.054 ;
    END
  END rw0_wd_in[151]
  PIN rw0_wd_in[152]
    DIRECTION INPUT ;
    USE SIGNAL ;
    SHAPE ABUTMENT ;
    PORT
      LAYER M3 ;
      RECT 12.303 0.000 12.321 0.054 ;
    END
  END rw0_wd_in[152]
  PIN rw0_wd_in[153]
    DIRECTION INPUT ;
    USE SIGNAL ;
    SHAPE ABUTMENT ;
    PORT
      LAYER M3 ;
      RECT 12.807 0.000 12.825 0.054 ;
    END
  END rw0_wd_in[153]
  PIN rw0_wd_in[154]
    DIRECTION INPUT ;
    USE SIGNAL ;
    SHAPE ABUTMENT ;
    PORT
      LAYER M3 ;
      RECT 13.311 0.000 13.329 0.054 ;
    END
  END rw0_wd_in[154]
  PIN rw0_wd_in[155]
    DIRECTION INPUT ;
    USE SIGNAL ;
    SHAPE ABUTMENT ;
    PORT
      LAYER M3 ;
      RECT 13.815 0.000 13.833 0.054 ;
    END
  END rw0_wd_in[155]
  PIN rw0_wd_in[156]
    DIRECTION INPUT ;
    USE SIGNAL ;
    SHAPE ABUTMENT ;
    PORT
      LAYER M3 ;
      RECT 14.319 0.000 14.337 0.054 ;
    END
  END rw0_wd_in[156]
  PIN rw0_wd_in[157]
    DIRECTION INPUT ;
    USE SIGNAL ;
    SHAPE ABUTMENT ;
    PORT
      LAYER M3 ;
      RECT 14.823 0.000 14.841 0.054 ;
    END
  END rw0_wd_in[157]
  PIN rw0_wd_in[158]
    DIRECTION INPUT ;
    USE SIGNAL ;
    SHAPE ABUTMENT ;
    PORT
      LAYER M3 ;
      RECT 15.327 0.000 15.345 0.054 ;
    END
  END rw0_wd_in[158]
  PIN rw0_wd_in[159]
    DIRECTION INPUT ;
    USE SIGNAL ;
    SHAPE ABUTMENT ;
    PORT
      LAYER M3 ;
      RECT 15.831 0.000 15.849 0.054 ;
    END
  END rw0_wd_in[159]
  PIN rw0_wd_in[160]
    DIRECTION INPUT ;
    USE SIGNAL ;
    SHAPE ABUTMENT ;
    PORT
      LAYER M3 ;
      RECT 16.335 0.000 16.353 0.054 ;
    END
  END rw0_wd_in[160]
  PIN rw0_wd_in[161]
    DIRECTION INPUT ;
    USE SIGNAL ;
    SHAPE ABUTMENT ;
    PORT
      LAYER M3 ;
      RECT 16.839 0.000 16.857 0.054 ;
    END
  END rw0_wd_in[161]
  PIN rw0_wd_in[162]
    DIRECTION INPUT ;
    USE SIGNAL ;
    SHAPE ABUTMENT ;
    PORT
      LAYER M3 ;
      RECT 17.343 0.000 17.361 0.054 ;
    END
  END rw0_wd_in[162]
  PIN rw0_wd_in[163]
    DIRECTION INPUT ;
    USE SIGNAL ;
    SHAPE ABUTMENT ;
    PORT
      LAYER M3 ;
      RECT 17.847 0.000 17.865 0.054 ;
    END
  END rw0_wd_in[163]
  PIN rw0_wd_in[164]
    DIRECTION INPUT ;
    USE SIGNAL ;
    SHAPE ABUTMENT ;
    PORT
      LAYER M3 ;
      RECT 18.351 0.000 18.369 0.054 ;
    END
  END rw0_wd_in[164]
  PIN rw0_wd_in[165]
    DIRECTION INPUT ;
    USE SIGNAL ;
    SHAPE ABUTMENT ;
    PORT
      LAYER M3 ;
      RECT 18.855 0.000 18.873 0.054 ;
    END
  END rw0_wd_in[165]
  PIN rw0_wd_in[166]
    DIRECTION INPUT ;
    USE SIGNAL ;
    SHAPE ABUTMENT ;
    PORT
      LAYER M3 ;
      RECT 19.359 0.000 19.377 0.054 ;
    END
  END rw0_wd_in[166]
  PIN rw0_wd_in[167]
    DIRECTION INPUT ;
    USE SIGNAL ;
    SHAPE ABUTMENT ;
    PORT
      LAYER M3 ;
      RECT 19.863 0.000 19.881 0.054 ;
    END
  END rw0_wd_in[167]
  PIN rw0_wd_in[168]
    DIRECTION INPUT ;
    USE SIGNAL ;
    SHAPE ABUTMENT ;
    PORT
      LAYER M3 ;
      RECT 20.367 0.000 20.385 0.054 ;
    END
  END rw0_wd_in[168]
  PIN rw0_wd_in[169]
    DIRECTION INPUT ;
    USE SIGNAL ;
    SHAPE ABUTMENT ;
    PORT
      LAYER M3 ;
      RECT 20.871 0.000 20.889 0.054 ;
    END
  END rw0_wd_in[169]
  PIN rw0_wd_in[170]
    DIRECTION INPUT ;
    USE SIGNAL ;
    SHAPE ABUTMENT ;
    PORT
      LAYER M3 ;
      RECT 21.375 0.000 21.393 0.054 ;
    END
  END rw0_wd_in[170]
  PIN rw0_wd_in[171]
    DIRECTION INPUT ;
    USE SIGNAL ;
    SHAPE ABUTMENT ;
    PORT
      LAYER M3 ;
      RECT 21.879 0.000 21.897 0.054 ;
    END
  END rw0_wd_in[171]
  PIN rw0_wd_in[172]
    DIRECTION INPUT ;
    USE SIGNAL ;
    SHAPE ABUTMENT ;
    PORT
      LAYER M3 ;
      RECT 22.383 0.000 22.401 0.054 ;
    END
  END rw0_wd_in[172]
  PIN rw0_wd_in[173]
    DIRECTION INPUT ;
    USE SIGNAL ;
    SHAPE ABUTMENT ;
    PORT
      LAYER M3 ;
      RECT 22.887 0.000 22.905 0.054 ;
    END
  END rw0_wd_in[173]
  PIN rw0_wd_in[174]
    DIRECTION INPUT ;
    USE SIGNAL ;
    SHAPE ABUTMENT ;
    PORT
      LAYER M3 ;
      RECT 23.391 0.000 23.409 0.054 ;
    END
  END rw0_wd_in[174]
  PIN rw0_wd_in[175]
    DIRECTION INPUT ;
    USE SIGNAL ;
    SHAPE ABUTMENT ;
    PORT
      LAYER M3 ;
      RECT 23.895 0.000 23.913 0.054 ;
    END
  END rw0_wd_in[175]
  PIN rw0_wd_in[176]
    DIRECTION INPUT ;
    USE SIGNAL ;
    SHAPE ABUTMENT ;
    PORT
      LAYER M3 ;
      RECT 24.399 0.000 24.417 0.054 ;
    END
  END rw0_wd_in[176]
  PIN rw0_wd_in[177]
    DIRECTION INPUT ;
    USE SIGNAL ;
    SHAPE ABUTMENT ;
    PORT
      LAYER M3 ;
      RECT 24.903 0.000 24.921 0.054 ;
    END
  END rw0_wd_in[177]
  PIN rw0_wd_in[178]
    DIRECTION INPUT ;
    USE SIGNAL ;
    SHAPE ABUTMENT ;
    PORT
      LAYER M3 ;
      RECT 25.407 0.000 25.425 0.054 ;
    END
  END rw0_wd_in[178]
  PIN rw0_wd_in[179]
    DIRECTION INPUT ;
    USE SIGNAL ;
    SHAPE ABUTMENT ;
    PORT
      LAYER M3 ;
      RECT 25.911 0.000 25.929 0.054 ;
    END
  END rw0_wd_in[179]
  PIN rw0_wd_in[180]
    DIRECTION INPUT ;
    USE SIGNAL ;
    SHAPE ABUTMENT ;
    PORT
      LAYER M3 ;
      RECT 26.415 0.000 26.433 0.054 ;
    END
  END rw0_wd_in[180]
  PIN rw0_wd_in[181]
    DIRECTION INPUT ;
    USE SIGNAL ;
    SHAPE ABUTMENT ;
    PORT
      LAYER M3 ;
      RECT 26.919 0.000 26.937 0.054 ;
    END
  END rw0_wd_in[181]
  PIN rw0_wd_in[182]
    DIRECTION INPUT ;
    USE SIGNAL ;
    SHAPE ABUTMENT ;
    PORT
      LAYER M3 ;
      RECT 27.423 0.000 27.441 0.054 ;
    END
  END rw0_wd_in[182]
  PIN rw0_wd_in[183]
    DIRECTION INPUT ;
    USE SIGNAL ;
    SHAPE ABUTMENT ;
    PORT
      LAYER M3 ;
      RECT 27.927 0.000 27.945 0.054 ;
    END
  END rw0_wd_in[183]
  PIN rw0_wd_in[184]
    DIRECTION INPUT ;
    USE SIGNAL ;
    SHAPE ABUTMENT ;
    PORT
      LAYER M3 ;
      RECT 28.431 0.000 28.449 0.054 ;
    END
  END rw0_wd_in[184]
  PIN rw0_wd_in[185]
    DIRECTION INPUT ;
    USE SIGNAL ;
    SHAPE ABUTMENT ;
    PORT
      LAYER M3 ;
      RECT 28.935 0.000 28.953 0.054 ;
    END
  END rw0_wd_in[185]
  PIN rw0_wd_in[186]
    DIRECTION INPUT ;
    USE SIGNAL ;
    SHAPE ABUTMENT ;
    PORT
      LAYER M3 ;
      RECT 29.439 0.000 29.457 0.054 ;
    END
  END rw0_wd_in[186]
  PIN rw0_wd_in[187]
    DIRECTION INPUT ;
    USE SIGNAL ;
    SHAPE ABUTMENT ;
    PORT
      LAYER M3 ;
      RECT 29.943 0.000 29.961 0.054 ;
    END
  END rw0_wd_in[187]
  PIN rw0_wd_in[188]
    DIRECTION INPUT ;
    USE SIGNAL ;
    SHAPE ABUTMENT ;
    PORT
      LAYER M3 ;
      RECT 30.447 0.000 30.465 0.054 ;
    END
  END rw0_wd_in[188]
  PIN rw0_wd_in[189]
    DIRECTION INPUT ;
    USE SIGNAL ;
    SHAPE ABUTMENT ;
    PORT
      LAYER M3 ;
      RECT 30.951 0.000 30.969 0.054 ;
    END
  END rw0_wd_in[189]
  PIN rw0_wd_in[190]
    DIRECTION INPUT ;
    USE SIGNAL ;
    SHAPE ABUTMENT ;
    PORT
      LAYER M3 ;
      RECT 31.455 0.000 31.473 0.054 ;
    END
  END rw0_wd_in[190]
  PIN rw0_wd_in[191]
    DIRECTION INPUT ;
    USE SIGNAL ;
    SHAPE ABUTMENT ;
    PORT
      LAYER M3 ;
      RECT 31.959 0.000 31.977 0.054 ;
    END
  END rw0_wd_in[191]
  PIN rw0_wd_in[192]
    DIRECTION INPUT ;
    USE SIGNAL ;
    SHAPE ABUTMENT ;
    PORT
      LAYER M3 ;
      RECT 32.463 0.000 32.481 0.054 ;
    END
  END rw0_wd_in[192]
  PIN rw0_wd_in[193]
    DIRECTION INPUT ;
    USE SIGNAL ;
    SHAPE ABUTMENT ;
    PORT
      LAYER M3 ;
      RECT 32.967 0.000 32.985 0.054 ;
    END
  END rw0_wd_in[193]
  PIN rw0_wd_in[194]
    DIRECTION INPUT ;
    USE SIGNAL ;
    SHAPE ABUTMENT ;
    PORT
      LAYER M3 ;
      RECT 33.471 0.000 33.489 0.054 ;
    END
  END rw0_wd_in[194]
  PIN rw0_wd_in[195]
    DIRECTION INPUT ;
    USE SIGNAL ;
    SHAPE ABUTMENT ;
    PORT
      LAYER M3 ;
      RECT 33.975 0.000 33.993 0.054 ;
    END
  END rw0_wd_in[195]
  PIN rw0_wd_in[196]
    DIRECTION INPUT ;
    USE SIGNAL ;
    SHAPE ABUTMENT ;
    PORT
      LAYER M3 ;
      RECT 34.479 0.000 34.497 0.054 ;
    END
  END rw0_wd_in[196]
  PIN rw0_wd_in[197]
    DIRECTION INPUT ;
    USE SIGNAL ;
    SHAPE ABUTMENT ;
    PORT
      LAYER M3 ;
      RECT 34.983 0.000 35.001 0.054 ;
    END
  END rw0_wd_in[197]
  PIN rw0_wd_in[198]
    DIRECTION INPUT ;
    USE SIGNAL ;
    SHAPE ABUTMENT ;
    PORT
      LAYER M3 ;
      RECT 35.487 0.000 35.505 0.054 ;
    END
  END rw0_wd_in[198]
  PIN rw0_wd_in[199]
    DIRECTION INPUT ;
    USE SIGNAL ;
    SHAPE ABUTMENT ;
    PORT
      LAYER M3 ;
      RECT 35.991 0.000 36.009 0.054 ;
    END
  END rw0_wd_in[199]
  PIN rw0_wd_in[200]
    DIRECTION INPUT ;
    USE SIGNAL ;
    SHAPE ABUTMENT ;
    PORT
      LAYER M3 ;
      RECT 36.495 0.000 36.513 0.054 ;
    END
  END rw0_wd_in[200]
  PIN rw0_wd_in[201]
    DIRECTION INPUT ;
    USE SIGNAL ;
    SHAPE ABUTMENT ;
    PORT
      LAYER M3 ;
      RECT 36.999 0.000 37.017 0.054 ;
    END
  END rw0_wd_in[201]
  PIN rw0_wd_in[202]
    DIRECTION INPUT ;
    USE SIGNAL ;
    SHAPE ABUTMENT ;
    PORT
      LAYER M3 ;
      RECT 37.503 0.000 37.521 0.054 ;
    END
  END rw0_wd_in[202]
  PIN rw0_wd_in[203]
    DIRECTION INPUT ;
    USE SIGNAL ;
    SHAPE ABUTMENT ;
    PORT
      LAYER M3 ;
      RECT 38.007 0.000 38.025 0.054 ;
    END
  END rw0_wd_in[203]
  PIN rw0_wd_in[204]
    DIRECTION INPUT ;
    USE SIGNAL ;
    SHAPE ABUTMENT ;
    PORT
      LAYER M3 ;
      RECT 38.511 0.000 38.529 0.054 ;
    END
  END rw0_wd_in[204]
  PIN rw0_wd_in[205]
    DIRECTION INPUT ;
    USE SIGNAL ;
    SHAPE ABUTMENT ;
    PORT
      LAYER M3 ;
      RECT 39.015 0.000 39.033 0.054 ;
    END
  END rw0_wd_in[205]
  PIN rw0_wd_in[206]
    DIRECTION INPUT ;
    USE SIGNAL ;
    SHAPE ABUTMENT ;
    PORT
      LAYER M3 ;
      RECT 39.519 0.000 39.537 0.054 ;
    END
  END rw0_wd_in[206]
  PIN rw0_wd_in[207]
    DIRECTION INPUT ;
    USE SIGNAL ;
    SHAPE ABUTMENT ;
    PORT
      LAYER M3 ;
      RECT 40.023 0.000 40.041 0.054 ;
    END
  END rw0_wd_in[207]
  PIN rw0_wd_in[208]
    DIRECTION INPUT ;
    USE SIGNAL ;
    SHAPE ABUTMENT ;
    PORT
      LAYER M3 ;
      RECT 40.527 0.000 40.545 0.054 ;
    END
  END rw0_wd_in[208]
  PIN rw0_wd_in[209]
    DIRECTION INPUT ;
    USE SIGNAL ;
    SHAPE ABUTMENT ;
    PORT
      LAYER M3 ;
      RECT 41.031 0.000 41.049 0.054 ;
    END
  END rw0_wd_in[209]
  PIN rw0_wd_in[210]
    DIRECTION INPUT ;
    USE SIGNAL ;
    SHAPE ABUTMENT ;
    PORT
      LAYER M3 ;
      RECT 41.535 0.000 41.553 0.054 ;
    END
  END rw0_wd_in[210]
  PIN rw0_wd_in[211]
    DIRECTION INPUT ;
    USE SIGNAL ;
    SHAPE ABUTMENT ;
    PORT
      LAYER M3 ;
      RECT 42.039 0.000 42.057 0.054 ;
    END
  END rw0_wd_in[211]
  PIN rw0_wd_in[212]
    DIRECTION INPUT ;
    USE SIGNAL ;
    SHAPE ABUTMENT ;
    PORT
      LAYER M3 ;
      RECT 42.543 0.000 42.561 0.054 ;
    END
  END rw0_wd_in[212]
  PIN rw0_wd_in[213]
    DIRECTION INPUT ;
    USE SIGNAL ;
    SHAPE ABUTMENT ;
    PORT
      LAYER M3 ;
      RECT 43.047 0.000 43.065 0.054 ;
    END
  END rw0_wd_in[213]
  PIN rw0_wd_in[214]
    DIRECTION INPUT ;
    USE SIGNAL ;
    SHAPE ABUTMENT ;
    PORT
      LAYER M3 ;
      RECT 43.551 0.000 43.569 0.054 ;
    END
  END rw0_wd_in[214]
  PIN rw0_wd_in[215]
    DIRECTION INPUT ;
    USE SIGNAL ;
    SHAPE ABUTMENT ;
    PORT
      LAYER M3 ;
      RECT 44.055 0.000 44.073 0.054 ;
    END
  END rw0_wd_in[215]
  PIN rw0_wd_in[216]
    DIRECTION INPUT ;
    USE SIGNAL ;
    SHAPE ABUTMENT ;
    PORT
      LAYER M3 ;
      RECT 44.559 0.000 44.577 0.054 ;
    END
  END rw0_wd_in[216]
  PIN rw0_wd_in[217]
    DIRECTION INPUT ;
    USE SIGNAL ;
    SHAPE ABUTMENT ;
    PORT
      LAYER M3 ;
      RECT 45.063 0.000 45.081 0.054 ;
    END
  END rw0_wd_in[217]
  PIN rw0_wd_in[218]
    DIRECTION INPUT ;
    USE SIGNAL ;
    SHAPE ABUTMENT ;
    PORT
      LAYER M3 ;
      RECT 45.567 0.000 45.585 0.054 ;
    END
  END rw0_wd_in[218]
  PIN rw0_wd_in[219]
    DIRECTION INPUT ;
    USE SIGNAL ;
    SHAPE ABUTMENT ;
    PORT
      LAYER M3 ;
      RECT 46.071 0.000 46.089 0.054 ;
    END
  END rw0_wd_in[219]
  PIN rw0_wd_in[220]
    DIRECTION INPUT ;
    USE SIGNAL ;
    SHAPE ABUTMENT ;
    PORT
      LAYER M3 ;
      RECT 46.575 0.000 46.593 0.054 ;
    END
  END rw0_wd_in[220]
  PIN rw0_wd_in[221]
    DIRECTION INPUT ;
    USE SIGNAL ;
    SHAPE ABUTMENT ;
    PORT
      LAYER M3 ;
      RECT 47.079 0.000 47.097 0.054 ;
    END
  END rw0_wd_in[221]
  PIN rw0_wd_in[222]
    DIRECTION INPUT ;
    USE SIGNAL ;
    SHAPE ABUTMENT ;
    PORT
      LAYER M3 ;
      RECT 47.583 0.000 47.601 0.054 ;
    END
  END rw0_wd_in[222]
  PIN rw0_wd_in[223]
    DIRECTION INPUT ;
    USE SIGNAL ;
    SHAPE ABUTMENT ;
    PORT
      LAYER M3 ;
      RECT 48.087 0.000 48.105 0.054 ;
    END
  END rw0_wd_in[223]
  PIN rw0_wd_in[224]
    DIRECTION INPUT ;
    USE SIGNAL ;
    SHAPE ABUTMENT ;
    PORT
      LAYER M3 ;
      RECT 48.591 0.000 48.609 0.054 ;
    END
  END rw0_wd_in[224]
  PIN rw0_wd_in[225]
    DIRECTION INPUT ;
    USE SIGNAL ;
    SHAPE ABUTMENT ;
    PORT
      LAYER M3 ;
      RECT 49.095 0.000 49.113 0.054 ;
    END
  END rw0_wd_in[225]
  PIN rw0_wd_in[226]
    DIRECTION INPUT ;
    USE SIGNAL ;
    SHAPE ABUTMENT ;
    PORT
      LAYER M3 ;
      RECT 49.599 0.000 49.617 0.054 ;
    END
  END rw0_wd_in[226]
  PIN rw0_wd_in[227]
    DIRECTION INPUT ;
    USE SIGNAL ;
    SHAPE ABUTMENT ;
    PORT
      LAYER M3 ;
      RECT 50.103 0.000 50.121 0.054 ;
    END
  END rw0_wd_in[227]
  PIN rw0_wd_in[228]
    DIRECTION INPUT ;
    USE SIGNAL ;
    SHAPE ABUTMENT ;
    PORT
      LAYER M3 ;
      RECT 50.607 0.000 50.625 0.054 ;
    END
  END rw0_wd_in[228]
  PIN rw0_wd_in[229]
    DIRECTION INPUT ;
    USE SIGNAL ;
    SHAPE ABUTMENT ;
    PORT
      LAYER M3 ;
      RECT 51.111 0.000 51.129 0.054 ;
    END
  END rw0_wd_in[229]
  PIN rw0_wd_in[230]
    DIRECTION INPUT ;
    USE SIGNAL ;
    SHAPE ABUTMENT ;
    PORT
      LAYER M3 ;
      RECT 51.615 0.000 51.633 0.054 ;
    END
  END rw0_wd_in[230]
  PIN rw0_wd_in[231]
    DIRECTION INPUT ;
    USE SIGNAL ;
    SHAPE ABUTMENT ;
    PORT
      LAYER M3 ;
      RECT 52.119 0.000 52.137 0.054 ;
    END
  END rw0_wd_in[231]
  PIN rw0_wd_in[232]
    DIRECTION INPUT ;
    USE SIGNAL ;
    SHAPE ABUTMENT ;
    PORT
      LAYER M3 ;
      RECT 52.623 0.000 52.641 0.054 ;
    END
  END rw0_wd_in[232]
  PIN rw0_wd_in[233]
    DIRECTION INPUT ;
    USE SIGNAL ;
    SHAPE ABUTMENT ;
    PORT
      LAYER M3 ;
      RECT 53.127 0.000 53.145 0.054 ;
    END
  END rw0_wd_in[233]
  PIN rw0_wd_in[234]
    DIRECTION INPUT ;
    USE SIGNAL ;
    SHAPE ABUTMENT ;
    PORT
      LAYER M3 ;
      RECT 53.631 0.000 53.649 0.054 ;
    END
  END rw0_wd_in[234]
  PIN rw0_wd_in[235]
    DIRECTION INPUT ;
    USE SIGNAL ;
    SHAPE ABUTMENT ;
    PORT
      LAYER M3 ;
      RECT 54.135 0.000 54.153 0.054 ;
    END
  END rw0_wd_in[235]
  PIN rw0_wd_in[236]
    DIRECTION INPUT ;
    USE SIGNAL ;
    SHAPE ABUTMENT ;
    PORT
      LAYER M3 ;
      RECT 54.639 0.000 54.657 0.054 ;
    END
  END rw0_wd_in[236]
  PIN rw0_wd_in[237]
    DIRECTION INPUT ;
    USE SIGNAL ;
    SHAPE ABUTMENT ;
    PORT
      LAYER M3 ;
      RECT 55.143 0.000 55.161 0.054 ;
    END
  END rw0_wd_in[237]
  PIN rw0_wd_in[238]
    DIRECTION INPUT ;
    USE SIGNAL ;
    SHAPE ABUTMENT ;
    PORT
      LAYER M3 ;
      RECT 55.647 0.000 55.665 0.054 ;
    END
  END rw0_wd_in[238]
  PIN rw0_wd_in[239]
    DIRECTION INPUT ;
    USE SIGNAL ;
    SHAPE ABUTMENT ;
    PORT
      LAYER M3 ;
      RECT 56.151 0.000 56.169 0.054 ;
    END
  END rw0_wd_in[239]
  PIN rw0_wd_in[240]
    DIRECTION INPUT ;
    USE SIGNAL ;
    SHAPE ABUTMENT ;
    PORT
      LAYER M3 ;
      RECT 56.655 0.000 56.673 0.054 ;
    END
  END rw0_wd_in[240]
  PIN rw0_wd_in[241]
    DIRECTION INPUT ;
    USE SIGNAL ;
    SHAPE ABUTMENT ;
    PORT
      LAYER M3 ;
      RECT 57.159 0.000 57.177 0.054 ;
    END
  END rw0_wd_in[241]
  PIN rw0_wd_in[242]
    DIRECTION INPUT ;
    USE SIGNAL ;
    SHAPE ABUTMENT ;
    PORT
      LAYER M3 ;
      RECT 57.663 0.000 57.681 0.054 ;
    END
  END rw0_wd_in[242]
  PIN rw0_wd_in[243]
    DIRECTION INPUT ;
    USE SIGNAL ;
    SHAPE ABUTMENT ;
    PORT
      LAYER M3 ;
      RECT 58.167 0.000 58.185 0.054 ;
    END
  END rw0_wd_in[243]
  PIN rw0_wd_in[244]
    DIRECTION INPUT ;
    USE SIGNAL ;
    SHAPE ABUTMENT ;
    PORT
      LAYER M3 ;
      RECT 58.671 0.000 58.689 0.054 ;
    END
  END rw0_wd_in[244]
  PIN rw0_wd_in[245]
    DIRECTION INPUT ;
    USE SIGNAL ;
    SHAPE ABUTMENT ;
    PORT
      LAYER M3 ;
      RECT 59.175 0.000 59.193 0.054 ;
    END
  END rw0_wd_in[245]
  PIN rw0_wd_in[246]
    DIRECTION INPUT ;
    USE SIGNAL ;
    SHAPE ABUTMENT ;
    PORT
      LAYER M3 ;
      RECT 59.679 0.000 59.697 0.054 ;
    END
  END rw0_wd_in[246]
  PIN rw0_wd_in[247]
    DIRECTION INPUT ;
    USE SIGNAL ;
    SHAPE ABUTMENT ;
    PORT
      LAYER M3 ;
      RECT 60.183 0.000 60.201 0.054 ;
    END
  END rw0_wd_in[247]
  PIN rw0_wd_in[248]
    DIRECTION INPUT ;
    USE SIGNAL ;
    SHAPE ABUTMENT ;
    PORT
      LAYER M3 ;
      RECT 60.687 0.000 60.705 0.054 ;
    END
  END rw0_wd_in[248]
  PIN rw0_wd_in[249]
    DIRECTION INPUT ;
    USE SIGNAL ;
    SHAPE ABUTMENT ;
    PORT
      LAYER M3 ;
      RECT 61.191 0.000 61.209 0.054 ;
    END
  END rw0_wd_in[249]
  PIN rw0_wd_in[250]
    DIRECTION INPUT ;
    USE SIGNAL ;
    SHAPE ABUTMENT ;
    PORT
      LAYER M3 ;
      RECT 61.695 0.000 61.713 0.054 ;
    END
  END rw0_wd_in[250]
  PIN rw0_wd_in[251]
    DIRECTION INPUT ;
    USE SIGNAL ;
    SHAPE ABUTMENT ;
    PORT
      LAYER M3 ;
      RECT 62.199 0.000 62.217 0.054 ;
    END
  END rw0_wd_in[251]
  PIN rw0_wd_in[252]
    DIRECTION INPUT ;
    USE SIGNAL ;
    SHAPE ABUTMENT ;
    PORT
      LAYER M3 ;
      RECT 62.703 0.000 62.721 0.054 ;
    END
  END rw0_wd_in[252]
  PIN rw0_wd_in[253]
    DIRECTION INPUT ;
    USE SIGNAL ;
    SHAPE ABUTMENT ;
    PORT
      LAYER M3 ;
      RECT 63.207 0.000 63.225 0.054 ;
    END
  END rw0_wd_in[253]
  PIN rw0_wd_in[254]
    DIRECTION INPUT ;
    USE SIGNAL ;
    SHAPE ABUTMENT ;
    PORT
      LAYER M3 ;
      RECT 63.711 0.000 63.729 0.054 ;
    END
  END rw0_wd_in[254]
  PIN rw0_wd_in[255]
    DIRECTION INPUT ;
    USE SIGNAL ;
    SHAPE ABUTMENT ;
    PORT
      LAYER M3 ;
      RECT 64.215 0.000 64.233 0.054 ;
    END
  END rw0_wd_in[255]
  PIN rw0_rd_out[0]
    DIRECTION OUTPUT ;
    USE SIGNAL ;
    SHAPE ABUTMENT ;
    PORT
      LAYER M3 ;
      RECT 64.719 0.000 64.737 0.054 ;
    END
  END rw0_rd_out[0]
  PIN rw0_rd_out[1]
    DIRECTION OUTPUT ;
    USE SIGNAL ;
    SHAPE ABUTMENT ;
    PORT
      LAYER M3 ;
      RECT 65.223 0.000 65.241 0.054 ;
    END
  END rw0_rd_out[1]
  PIN rw0_rd_out[2]
    DIRECTION OUTPUT ;
    USE SIGNAL ;
    SHAPE ABUTMENT ;
    PORT
      LAYER M3 ;
      RECT 65.727 0.000 65.745 0.054 ;
    END
  END rw0_rd_out[2]
  PIN rw0_rd_out[3]
    DIRECTION OUTPUT ;
    USE SIGNAL ;
    SHAPE ABUTMENT ;
    PORT
      LAYER M3 ;
      RECT 66.231 0.000 66.249 0.054 ;
    END
  END rw0_rd_out[3]
  PIN rw0_rd_out[4]
    DIRECTION OUTPUT ;
    USE SIGNAL ;
    SHAPE ABUTMENT ;
    PORT
      LAYER M3 ;
      RECT 66.735 0.000 66.753 0.054 ;
    END
  END rw0_rd_out[4]
  PIN rw0_rd_out[5]
    DIRECTION OUTPUT ;
    USE SIGNAL ;
    SHAPE ABUTMENT ;
    PORT
      LAYER M3 ;
      RECT 67.239 0.000 67.257 0.054 ;
    END
  END rw0_rd_out[5]
  PIN rw0_rd_out[6]
    DIRECTION OUTPUT ;
    USE SIGNAL ;
    SHAPE ABUTMENT ;
    PORT
      LAYER M3 ;
      RECT 67.743 0.000 67.761 0.054 ;
    END
  END rw0_rd_out[6]
  PIN rw0_rd_out[7]
    DIRECTION OUTPUT ;
    USE SIGNAL ;
    SHAPE ABUTMENT ;
    PORT
      LAYER M3 ;
      RECT 68.247 0.000 68.265 0.054 ;
    END
  END rw0_rd_out[7]
  PIN rw0_rd_out[8]
    DIRECTION OUTPUT ;
    USE SIGNAL ;
    SHAPE ABUTMENT ;
    PORT
      LAYER M3 ;
      RECT 68.751 0.000 68.769 0.054 ;
    END
  END rw0_rd_out[8]
  PIN rw0_rd_out[9]
    DIRECTION OUTPUT ;
    USE SIGNAL ;
    SHAPE ABUTMENT ;
    PORT
      LAYER M3 ;
      RECT 69.255 0.000 69.273 0.054 ;
    END
  END rw0_rd_out[9]
  PIN rw0_rd_out[10]
    DIRECTION OUTPUT ;
    USE SIGNAL ;
    SHAPE ABUTMENT ;
    PORT
      LAYER M3 ;
      RECT 69.759 0.000 69.777 0.054 ;
    END
  END rw0_rd_out[10]
  PIN rw0_rd_out[11]
    DIRECTION OUTPUT ;
    USE SIGNAL ;
    SHAPE ABUTMENT ;
    PORT
      LAYER M3 ;
      RECT 70.263 0.000 70.281 0.054 ;
    END
  END rw0_rd_out[11]
  PIN rw0_rd_out[12]
    DIRECTION OUTPUT ;
    USE SIGNAL ;
    SHAPE ABUTMENT ;
    PORT
      LAYER M3 ;
      RECT 70.767 0.000 70.785 0.054 ;
    END
  END rw0_rd_out[12]
  PIN rw0_rd_out[13]
    DIRECTION OUTPUT ;
    USE SIGNAL ;
    SHAPE ABUTMENT ;
    PORT
      LAYER M3 ;
      RECT 71.271 0.000 71.289 0.054 ;
    END
  END rw0_rd_out[13]
  PIN rw0_rd_out[14]
    DIRECTION OUTPUT ;
    USE SIGNAL ;
    SHAPE ABUTMENT ;
    PORT
      LAYER M3 ;
      RECT 71.775 0.000 71.793 0.054 ;
    END
  END rw0_rd_out[14]
  PIN rw0_rd_out[15]
    DIRECTION OUTPUT ;
    USE SIGNAL ;
    SHAPE ABUTMENT ;
    PORT
      LAYER M3 ;
      RECT 72.279 0.000 72.297 0.054 ;
    END
  END rw0_rd_out[15]
  PIN rw0_rd_out[16]
    DIRECTION OUTPUT ;
    USE SIGNAL ;
    SHAPE ABUTMENT ;
    PORT
      LAYER M3 ;
      RECT 72.783 0.000 72.801 0.054 ;
    END
  END rw0_rd_out[16]
  PIN rw0_rd_out[17]
    DIRECTION OUTPUT ;
    USE SIGNAL ;
    SHAPE ABUTMENT ;
    PORT
      LAYER M3 ;
      RECT 73.287 0.000 73.305 0.054 ;
    END
  END rw0_rd_out[17]
  PIN rw0_rd_out[18]
    DIRECTION OUTPUT ;
    USE SIGNAL ;
    SHAPE ABUTMENT ;
    PORT
      LAYER M3 ;
      RECT 73.791 0.000 73.809 0.054 ;
    END
  END rw0_rd_out[18]
  PIN rw0_rd_out[19]
    DIRECTION OUTPUT ;
    USE SIGNAL ;
    SHAPE ABUTMENT ;
    PORT
      LAYER M3 ;
      RECT 74.295 0.000 74.313 0.054 ;
    END
  END rw0_rd_out[19]
  PIN rw0_rd_out[20]
    DIRECTION OUTPUT ;
    USE SIGNAL ;
    SHAPE ABUTMENT ;
    PORT
      LAYER M3 ;
      RECT 74.799 0.000 74.817 0.054 ;
    END
  END rw0_rd_out[20]
  PIN rw0_rd_out[21]
    DIRECTION OUTPUT ;
    USE SIGNAL ;
    SHAPE ABUTMENT ;
    PORT
      LAYER M3 ;
      RECT 75.303 0.000 75.321 0.054 ;
    END
  END rw0_rd_out[21]
  PIN rw0_rd_out[22]
    DIRECTION OUTPUT ;
    USE SIGNAL ;
    SHAPE ABUTMENT ;
    PORT
      LAYER M3 ;
      RECT 75.807 0.000 75.825 0.054 ;
    END
  END rw0_rd_out[22]
  PIN rw0_rd_out[23]
    DIRECTION OUTPUT ;
    USE SIGNAL ;
    SHAPE ABUTMENT ;
    PORT
      LAYER M3 ;
      RECT 76.311 0.000 76.329 0.054 ;
    END
  END rw0_rd_out[23]
  PIN rw0_rd_out[24]
    DIRECTION OUTPUT ;
    USE SIGNAL ;
    SHAPE ABUTMENT ;
    PORT
      LAYER M3 ;
      RECT 76.815 0.000 76.833 0.054 ;
    END
  END rw0_rd_out[24]
  PIN rw0_rd_out[25]
    DIRECTION OUTPUT ;
    USE SIGNAL ;
    SHAPE ABUTMENT ;
    PORT
      LAYER M3 ;
      RECT 77.319 0.000 77.337 0.054 ;
    END
  END rw0_rd_out[25]
  PIN rw0_rd_out[26]
    DIRECTION OUTPUT ;
    USE SIGNAL ;
    SHAPE ABUTMENT ;
    PORT
      LAYER M3 ;
      RECT 77.823 0.000 77.841 0.054 ;
    END
  END rw0_rd_out[26]
  PIN rw0_rd_out[27]
    DIRECTION OUTPUT ;
    USE SIGNAL ;
    SHAPE ABUTMENT ;
    PORT
      LAYER M3 ;
      RECT 78.327 0.000 78.345 0.054 ;
    END
  END rw0_rd_out[27]
  PIN rw0_rd_out[28]
    DIRECTION OUTPUT ;
    USE SIGNAL ;
    SHAPE ABUTMENT ;
    PORT
      LAYER M3 ;
      RECT 78.831 0.000 78.849 0.054 ;
    END
  END rw0_rd_out[28]
  PIN rw0_rd_out[29]
    DIRECTION OUTPUT ;
    USE SIGNAL ;
    SHAPE ABUTMENT ;
    PORT
      LAYER M3 ;
      RECT 79.335 0.000 79.353 0.054 ;
    END
  END rw0_rd_out[29]
  PIN rw0_rd_out[30]
    DIRECTION OUTPUT ;
    USE SIGNAL ;
    SHAPE ABUTMENT ;
    PORT
      LAYER M3 ;
      RECT 79.839 0.000 79.857 0.054 ;
    END
  END rw0_rd_out[30]
  PIN rw0_rd_out[31]
    DIRECTION OUTPUT ;
    USE SIGNAL ;
    SHAPE ABUTMENT ;
    PORT
      LAYER M3 ;
      RECT 80.343 0.000 80.361 0.054 ;
    END
  END rw0_rd_out[31]
  PIN rw0_rd_out[32]
    DIRECTION OUTPUT ;
    USE SIGNAL ;
    SHAPE ABUTMENT ;
    PORT
      LAYER M3 ;
      RECT 80.847 0.000 80.865 0.054 ;
    END
  END rw0_rd_out[32]
  PIN rw0_rd_out[33]
    DIRECTION OUTPUT ;
    USE SIGNAL ;
    SHAPE ABUTMENT ;
    PORT
      LAYER M3 ;
      RECT 81.351 0.000 81.369 0.054 ;
    END
  END rw0_rd_out[33]
  PIN rw0_rd_out[34]
    DIRECTION OUTPUT ;
    USE SIGNAL ;
    SHAPE ABUTMENT ;
    PORT
      LAYER M3 ;
      RECT 81.855 0.000 81.873 0.054 ;
    END
  END rw0_rd_out[34]
  PIN rw0_rd_out[35]
    DIRECTION OUTPUT ;
    USE SIGNAL ;
    SHAPE ABUTMENT ;
    PORT
      LAYER M3 ;
      RECT 82.359 0.000 82.377 0.054 ;
    END
  END rw0_rd_out[35]
  PIN rw0_rd_out[36]
    DIRECTION OUTPUT ;
    USE SIGNAL ;
    SHAPE ABUTMENT ;
    PORT
      LAYER M3 ;
      RECT 82.863 0.000 82.881 0.054 ;
    END
  END rw0_rd_out[36]
  PIN rw0_rd_out[37]
    DIRECTION OUTPUT ;
    USE SIGNAL ;
    SHAPE ABUTMENT ;
    PORT
      LAYER M3 ;
      RECT 83.367 0.000 83.385 0.054 ;
    END
  END rw0_rd_out[37]
  PIN rw0_rd_out[38]
    DIRECTION OUTPUT ;
    USE SIGNAL ;
    SHAPE ABUTMENT ;
    PORT
      LAYER M3 ;
      RECT 83.871 0.000 83.889 0.054 ;
    END
  END rw0_rd_out[38]
  PIN rw0_rd_out[39]
    DIRECTION OUTPUT ;
    USE SIGNAL ;
    SHAPE ABUTMENT ;
    PORT
      LAYER M3 ;
      RECT 84.375 0.000 84.393 0.054 ;
    END
  END rw0_rd_out[39]
  PIN rw0_rd_out[40]
    DIRECTION OUTPUT ;
    USE SIGNAL ;
    SHAPE ABUTMENT ;
    PORT
      LAYER M3 ;
      RECT 84.879 0.000 84.897 0.054 ;
    END
  END rw0_rd_out[40]
  PIN rw0_rd_out[41]
    DIRECTION OUTPUT ;
    USE SIGNAL ;
    SHAPE ABUTMENT ;
    PORT
      LAYER M3 ;
      RECT 85.383 0.000 85.401 0.054 ;
    END
  END rw0_rd_out[41]
  PIN rw0_rd_out[42]
    DIRECTION OUTPUT ;
    USE SIGNAL ;
    SHAPE ABUTMENT ;
    PORT
      LAYER M3 ;
      RECT 85.887 0.000 85.905 0.054 ;
    END
  END rw0_rd_out[42]
  PIN rw0_rd_out[43]
    DIRECTION OUTPUT ;
    USE SIGNAL ;
    SHAPE ABUTMENT ;
    PORT
      LAYER M3 ;
      RECT 86.391 0.000 86.409 0.054 ;
    END
  END rw0_rd_out[43]
  PIN rw0_rd_out[44]
    DIRECTION OUTPUT ;
    USE SIGNAL ;
    SHAPE ABUTMENT ;
    PORT
      LAYER M3 ;
      RECT 86.895 0.000 86.913 0.054 ;
    END
  END rw0_rd_out[44]
  PIN rw0_rd_out[45]
    DIRECTION OUTPUT ;
    USE SIGNAL ;
    SHAPE ABUTMENT ;
    PORT
      LAYER M3 ;
      RECT 87.399 0.000 87.417 0.054 ;
    END
  END rw0_rd_out[45]
  PIN rw0_rd_out[46]
    DIRECTION OUTPUT ;
    USE SIGNAL ;
    SHAPE ABUTMENT ;
    PORT
      LAYER M3 ;
      RECT 87.903 0.000 87.921 0.054 ;
    END
  END rw0_rd_out[46]
  PIN rw0_rd_out[47]
    DIRECTION OUTPUT ;
    USE SIGNAL ;
    SHAPE ABUTMENT ;
    PORT
      LAYER M3 ;
      RECT 88.407 0.000 88.425 0.054 ;
    END
  END rw0_rd_out[47]
  PIN rw0_rd_out[48]
    DIRECTION OUTPUT ;
    USE SIGNAL ;
    SHAPE ABUTMENT ;
    PORT
      LAYER M3 ;
      RECT 88.911 0.000 88.929 0.054 ;
    END
  END rw0_rd_out[48]
  PIN rw0_rd_out[49]
    DIRECTION OUTPUT ;
    USE SIGNAL ;
    SHAPE ABUTMENT ;
    PORT
      LAYER M3 ;
      RECT 89.415 0.000 89.433 0.054 ;
    END
  END rw0_rd_out[49]
  PIN rw0_rd_out[50]
    DIRECTION OUTPUT ;
    USE SIGNAL ;
    SHAPE ABUTMENT ;
    PORT
      LAYER M3 ;
      RECT 89.919 0.000 89.937 0.054 ;
    END
  END rw0_rd_out[50]
  PIN rw0_rd_out[51]
    DIRECTION OUTPUT ;
    USE SIGNAL ;
    SHAPE ABUTMENT ;
    PORT
      LAYER M3 ;
      RECT 90.423 0.000 90.441 0.054 ;
    END
  END rw0_rd_out[51]
  PIN rw0_rd_out[52]
    DIRECTION OUTPUT ;
    USE SIGNAL ;
    SHAPE ABUTMENT ;
    PORT
      LAYER M3 ;
      RECT 90.927 0.000 90.945 0.054 ;
    END
  END rw0_rd_out[52]
  PIN rw0_rd_out[53]
    DIRECTION OUTPUT ;
    USE SIGNAL ;
    SHAPE ABUTMENT ;
    PORT
      LAYER M3 ;
      RECT 91.431 0.000 91.449 0.054 ;
    END
  END rw0_rd_out[53]
  PIN rw0_rd_out[54]
    DIRECTION OUTPUT ;
    USE SIGNAL ;
    SHAPE ABUTMENT ;
    PORT
      LAYER M3 ;
      RECT 91.935 0.000 91.953 0.054 ;
    END
  END rw0_rd_out[54]
  PIN rw0_rd_out[55]
    DIRECTION OUTPUT ;
    USE SIGNAL ;
    SHAPE ABUTMENT ;
    PORT
      LAYER M3 ;
      RECT 92.439 0.000 92.457 0.054 ;
    END
  END rw0_rd_out[55]
  PIN rw0_rd_out[56]
    DIRECTION OUTPUT ;
    USE SIGNAL ;
    SHAPE ABUTMENT ;
    PORT
      LAYER M3 ;
      RECT 92.943 0.000 92.961 0.054 ;
    END
  END rw0_rd_out[56]
  PIN rw0_rd_out[57]
    DIRECTION OUTPUT ;
    USE SIGNAL ;
    SHAPE ABUTMENT ;
    PORT
      LAYER M3 ;
      RECT 93.447 0.000 93.465 0.054 ;
    END
  END rw0_rd_out[57]
  PIN rw0_rd_out[58]
    DIRECTION OUTPUT ;
    USE SIGNAL ;
    SHAPE ABUTMENT ;
    PORT
      LAYER M3 ;
      RECT 93.951 0.000 93.969 0.054 ;
    END
  END rw0_rd_out[58]
  PIN rw0_rd_out[59]
    DIRECTION OUTPUT ;
    USE SIGNAL ;
    SHAPE ABUTMENT ;
    PORT
      LAYER M3 ;
      RECT 94.455 0.000 94.473 0.054 ;
    END
  END rw0_rd_out[59]
  PIN rw0_rd_out[60]
    DIRECTION OUTPUT ;
    USE SIGNAL ;
    SHAPE ABUTMENT ;
    PORT
      LAYER M3 ;
      RECT 94.959 0.000 94.977 0.054 ;
    END
  END rw0_rd_out[60]
  PIN rw0_rd_out[61]
    DIRECTION OUTPUT ;
    USE SIGNAL ;
    SHAPE ABUTMENT ;
    PORT
      LAYER M3 ;
      RECT 95.463 0.000 95.481 0.054 ;
    END
  END rw0_rd_out[61]
  PIN rw0_rd_out[62]
    DIRECTION OUTPUT ;
    USE SIGNAL ;
    SHAPE ABUTMENT ;
    PORT
      LAYER M3 ;
      RECT 95.967 0.000 95.985 0.054 ;
    END
  END rw0_rd_out[62]
  PIN rw0_rd_out[63]
    DIRECTION OUTPUT ;
    USE SIGNAL ;
    SHAPE ABUTMENT ;
    PORT
      LAYER M3 ;
      RECT 96.471 0.000 96.489 0.054 ;
    END
  END rw0_rd_out[63]
  PIN rw0_rd_out[64]
    DIRECTION OUTPUT ;
    USE SIGNAL ;
    SHAPE ABUTMENT ;
    PORT
      LAYER M3 ;
      RECT 96.975 0.000 96.993 0.054 ;
    END
  END rw0_rd_out[64]
  PIN rw0_rd_out[65]
    DIRECTION OUTPUT ;
    USE SIGNAL ;
    SHAPE ABUTMENT ;
    PORT
      LAYER M3 ;
      RECT 97.479 0.000 97.497 0.054 ;
    END
  END rw0_rd_out[65]
  PIN rw0_rd_out[66]
    DIRECTION OUTPUT ;
    USE SIGNAL ;
    SHAPE ABUTMENT ;
    PORT
      LAYER M3 ;
      RECT 97.983 0.000 98.001 0.054 ;
    END
  END rw0_rd_out[66]
  PIN rw0_rd_out[67]
    DIRECTION OUTPUT ;
    USE SIGNAL ;
    SHAPE ABUTMENT ;
    PORT
      LAYER M3 ;
      RECT 98.487 0.000 98.505 0.054 ;
    END
  END rw0_rd_out[67]
  PIN rw0_rd_out[68]
    DIRECTION OUTPUT ;
    USE SIGNAL ;
    SHAPE ABUTMENT ;
    PORT
      LAYER M3 ;
      RECT 98.991 0.000 99.009 0.054 ;
    END
  END rw0_rd_out[68]
  PIN rw0_rd_out[69]
    DIRECTION OUTPUT ;
    USE SIGNAL ;
    SHAPE ABUTMENT ;
    PORT
      LAYER M3 ;
      RECT 99.495 0.000 99.513 0.054 ;
    END
  END rw0_rd_out[69]
  PIN rw0_rd_out[70]
    DIRECTION OUTPUT ;
    USE SIGNAL ;
    SHAPE ABUTMENT ;
    PORT
      LAYER M3 ;
      RECT 99.999 0.000 100.017 0.054 ;
    END
  END rw0_rd_out[70]
  PIN rw0_rd_out[71]
    DIRECTION OUTPUT ;
    USE SIGNAL ;
    SHAPE ABUTMENT ;
    PORT
      LAYER M3 ;
      RECT 100.503 0.000 100.521 0.054 ;
    END
  END rw0_rd_out[71]
  PIN rw0_rd_out[72]
    DIRECTION OUTPUT ;
    USE SIGNAL ;
    SHAPE ABUTMENT ;
    PORT
      LAYER M3 ;
      RECT 101.007 0.000 101.025 0.054 ;
    END
  END rw0_rd_out[72]
  PIN rw0_rd_out[73]
    DIRECTION OUTPUT ;
    USE SIGNAL ;
    SHAPE ABUTMENT ;
    PORT
      LAYER M3 ;
      RECT 101.511 0.000 101.529 0.054 ;
    END
  END rw0_rd_out[73]
  PIN rw0_rd_out[74]
    DIRECTION OUTPUT ;
    USE SIGNAL ;
    SHAPE ABUTMENT ;
    PORT
      LAYER M3 ;
      RECT 102.015 0.000 102.033 0.054 ;
    END
  END rw0_rd_out[74]
  PIN rw0_rd_out[75]
    DIRECTION OUTPUT ;
    USE SIGNAL ;
    SHAPE ABUTMENT ;
    PORT
      LAYER M3 ;
      RECT 102.519 0.000 102.537 0.054 ;
    END
  END rw0_rd_out[75]
  PIN rw0_rd_out[76]
    DIRECTION OUTPUT ;
    USE SIGNAL ;
    SHAPE ABUTMENT ;
    PORT
      LAYER M3 ;
      RECT 103.023 0.000 103.041 0.054 ;
    END
  END rw0_rd_out[76]
  PIN rw0_rd_out[77]
    DIRECTION OUTPUT ;
    USE SIGNAL ;
    SHAPE ABUTMENT ;
    PORT
      LAYER M3 ;
      RECT 103.527 0.000 103.545 0.054 ;
    END
  END rw0_rd_out[77]
  PIN rw0_rd_out[78]
    DIRECTION OUTPUT ;
    USE SIGNAL ;
    SHAPE ABUTMENT ;
    PORT
      LAYER M3 ;
      RECT 104.031 0.000 104.049 0.054 ;
    END
  END rw0_rd_out[78]
  PIN rw0_rd_out[79]
    DIRECTION OUTPUT ;
    USE SIGNAL ;
    SHAPE ABUTMENT ;
    PORT
      LAYER M3 ;
      RECT 104.535 0.000 104.553 0.054 ;
    END
  END rw0_rd_out[79]
  PIN rw0_rd_out[80]
    DIRECTION OUTPUT ;
    USE SIGNAL ;
    SHAPE ABUTMENT ;
    PORT
      LAYER M3 ;
      RECT 105.039 0.000 105.057 0.054 ;
    END
  END rw0_rd_out[80]
  PIN rw0_rd_out[81]
    DIRECTION OUTPUT ;
    USE SIGNAL ;
    SHAPE ABUTMENT ;
    PORT
      LAYER M3 ;
      RECT 105.543 0.000 105.561 0.054 ;
    END
  END rw0_rd_out[81]
  PIN rw0_rd_out[82]
    DIRECTION OUTPUT ;
    USE SIGNAL ;
    SHAPE ABUTMENT ;
    PORT
      LAYER M3 ;
      RECT 106.047 0.000 106.065 0.054 ;
    END
  END rw0_rd_out[82]
  PIN rw0_rd_out[83]
    DIRECTION OUTPUT ;
    USE SIGNAL ;
    SHAPE ABUTMENT ;
    PORT
      LAYER M3 ;
      RECT 106.551 0.000 106.569 0.054 ;
    END
  END rw0_rd_out[83]
  PIN rw0_rd_out[84]
    DIRECTION OUTPUT ;
    USE SIGNAL ;
    SHAPE ABUTMENT ;
    PORT
      LAYER M3 ;
      RECT 107.055 0.000 107.073 0.054 ;
    END
  END rw0_rd_out[84]
  PIN rw0_rd_out[85]
    DIRECTION OUTPUT ;
    USE SIGNAL ;
    SHAPE ABUTMENT ;
    PORT
      LAYER M3 ;
      RECT 107.559 0.000 107.577 0.054 ;
    END
  END rw0_rd_out[85]
  PIN rw0_rd_out[86]
    DIRECTION OUTPUT ;
    USE SIGNAL ;
    SHAPE ABUTMENT ;
    PORT
      LAYER M3 ;
      RECT 108.063 0.000 108.081 0.054 ;
    END
  END rw0_rd_out[86]
  PIN rw0_rd_out[87]
    DIRECTION OUTPUT ;
    USE SIGNAL ;
    SHAPE ABUTMENT ;
    PORT
      LAYER M3 ;
      RECT 108.567 0.000 108.585 0.054 ;
    END
  END rw0_rd_out[87]
  PIN rw0_rd_out[88]
    DIRECTION OUTPUT ;
    USE SIGNAL ;
    SHAPE ABUTMENT ;
    PORT
      LAYER M3 ;
      RECT 109.071 0.000 109.089 0.054 ;
    END
  END rw0_rd_out[88]
  PIN rw0_rd_out[89]
    DIRECTION OUTPUT ;
    USE SIGNAL ;
    SHAPE ABUTMENT ;
    PORT
      LAYER M3 ;
      RECT 109.575 0.000 109.593 0.054 ;
    END
  END rw0_rd_out[89]
  PIN rw0_rd_out[90]
    DIRECTION OUTPUT ;
    USE SIGNAL ;
    SHAPE ABUTMENT ;
    PORT
      LAYER M3 ;
      RECT 110.079 0.000 110.097 0.054 ;
    END
  END rw0_rd_out[90]
  PIN rw0_rd_out[91]
    DIRECTION OUTPUT ;
    USE SIGNAL ;
    SHAPE ABUTMENT ;
    PORT
      LAYER M3 ;
      RECT 110.583 0.000 110.601 0.054 ;
    END
  END rw0_rd_out[91]
  PIN rw0_rd_out[92]
    DIRECTION OUTPUT ;
    USE SIGNAL ;
    SHAPE ABUTMENT ;
    PORT
      LAYER M3 ;
      RECT 111.087 0.000 111.105 0.054 ;
    END
  END rw0_rd_out[92]
  PIN rw0_rd_out[93]
    DIRECTION OUTPUT ;
    USE SIGNAL ;
    SHAPE ABUTMENT ;
    PORT
      LAYER M3 ;
      RECT 111.591 0.000 111.609 0.054 ;
    END
  END rw0_rd_out[93]
  PIN rw0_rd_out[94]
    DIRECTION OUTPUT ;
    USE SIGNAL ;
    SHAPE ABUTMENT ;
    PORT
      LAYER M3 ;
      RECT 112.095 0.000 112.113 0.054 ;
    END
  END rw0_rd_out[94]
  PIN rw0_rd_out[95]
    DIRECTION OUTPUT ;
    USE SIGNAL ;
    SHAPE ABUTMENT ;
    PORT
      LAYER M3 ;
      RECT 112.599 0.000 112.617 0.054 ;
    END
  END rw0_rd_out[95]
  PIN rw0_rd_out[96]
    DIRECTION OUTPUT ;
    USE SIGNAL ;
    SHAPE ABUTMENT ;
    PORT
      LAYER M3 ;
      RECT 113.103 0.000 113.121 0.054 ;
    END
  END rw0_rd_out[96]
  PIN rw0_rd_out[97]
    DIRECTION OUTPUT ;
    USE SIGNAL ;
    SHAPE ABUTMENT ;
    PORT
      LAYER M3 ;
      RECT 113.607 0.000 113.625 0.054 ;
    END
  END rw0_rd_out[97]
  PIN rw0_rd_out[98]
    DIRECTION OUTPUT ;
    USE SIGNAL ;
    SHAPE ABUTMENT ;
    PORT
      LAYER M3 ;
      RECT 114.111 0.000 114.129 0.054 ;
    END
  END rw0_rd_out[98]
  PIN rw0_rd_out[99]
    DIRECTION OUTPUT ;
    USE SIGNAL ;
    SHAPE ABUTMENT ;
    PORT
      LAYER M3 ;
      RECT 114.615 0.000 114.633 0.054 ;
    END
  END rw0_rd_out[99]
  PIN rw0_rd_out[100]
    DIRECTION OUTPUT ;
    USE SIGNAL ;
    SHAPE ABUTMENT ;
    PORT
      LAYER M3 ;
      RECT 115.119 0.000 115.137 0.054 ;
    END
  END rw0_rd_out[100]
  PIN rw0_rd_out[101]
    DIRECTION OUTPUT ;
    USE SIGNAL ;
    SHAPE ABUTMENT ;
    PORT
      LAYER M3 ;
      RECT 115.623 0.000 115.641 0.054 ;
    END
  END rw0_rd_out[101]
  PIN rw0_rd_out[102]
    DIRECTION OUTPUT ;
    USE SIGNAL ;
    SHAPE ABUTMENT ;
    PORT
      LAYER M3 ;
      RECT 116.127 0.000 116.145 0.054 ;
    END
  END rw0_rd_out[102]
  PIN rw0_rd_out[103]
    DIRECTION OUTPUT ;
    USE SIGNAL ;
    SHAPE ABUTMENT ;
    PORT
      LAYER M3 ;
      RECT 116.631 0.000 116.649 0.054 ;
    END
  END rw0_rd_out[103]
  PIN rw0_rd_out[104]
    DIRECTION OUTPUT ;
    USE SIGNAL ;
    SHAPE ABUTMENT ;
    PORT
      LAYER M3 ;
      RECT 117.135 0.000 117.153 0.054 ;
    END
  END rw0_rd_out[104]
  PIN rw0_rd_out[105]
    DIRECTION OUTPUT ;
    USE SIGNAL ;
    SHAPE ABUTMENT ;
    PORT
      LAYER M3 ;
      RECT 117.639 0.000 117.657 0.054 ;
    END
  END rw0_rd_out[105]
  PIN rw0_rd_out[106]
    DIRECTION OUTPUT ;
    USE SIGNAL ;
    SHAPE ABUTMENT ;
    PORT
      LAYER M3 ;
      RECT 118.143 0.000 118.161 0.054 ;
    END
  END rw0_rd_out[106]
  PIN rw0_rd_out[107]
    DIRECTION OUTPUT ;
    USE SIGNAL ;
    SHAPE ABUTMENT ;
    PORT
      LAYER M3 ;
      RECT 118.647 0.000 118.665 0.054 ;
    END
  END rw0_rd_out[107]
  PIN rw0_rd_out[108]
    DIRECTION OUTPUT ;
    USE SIGNAL ;
    SHAPE ABUTMENT ;
    PORT
      LAYER M3 ;
      RECT 119.151 0.000 119.169 0.054 ;
    END
  END rw0_rd_out[108]
  PIN rw0_rd_out[109]
    DIRECTION OUTPUT ;
    USE SIGNAL ;
    SHAPE ABUTMENT ;
    PORT
      LAYER M3 ;
      RECT 119.655 0.000 119.673 0.054 ;
    END
  END rw0_rd_out[109]
  PIN rw0_rd_out[110]
    DIRECTION OUTPUT ;
    USE SIGNAL ;
    SHAPE ABUTMENT ;
    PORT
      LAYER M3 ;
      RECT 120.159 0.000 120.177 0.054 ;
    END
  END rw0_rd_out[110]
  PIN rw0_rd_out[111]
    DIRECTION OUTPUT ;
    USE SIGNAL ;
    SHAPE ABUTMENT ;
    PORT
      LAYER M3 ;
      RECT 120.663 0.000 120.681 0.054 ;
    END
  END rw0_rd_out[111]
  PIN rw0_rd_out[112]
    DIRECTION OUTPUT ;
    USE SIGNAL ;
    SHAPE ABUTMENT ;
    PORT
      LAYER M3 ;
      RECT 121.167 0.000 121.185 0.054 ;
    END
  END rw0_rd_out[112]
  PIN rw0_rd_out[113]
    DIRECTION OUTPUT ;
    USE SIGNAL ;
    SHAPE ABUTMENT ;
    PORT
      LAYER M3 ;
      RECT 121.671 0.000 121.689 0.054 ;
    END
  END rw0_rd_out[113]
  PIN rw0_rd_out[114]
    DIRECTION OUTPUT ;
    USE SIGNAL ;
    SHAPE ABUTMENT ;
    PORT
      LAYER M3 ;
      RECT 122.175 0.000 122.193 0.054 ;
    END
  END rw0_rd_out[114]
  PIN rw0_rd_out[115]
    DIRECTION OUTPUT ;
    USE SIGNAL ;
    SHAPE ABUTMENT ;
    PORT
      LAYER M3 ;
      RECT 122.679 0.000 122.697 0.054 ;
    END
  END rw0_rd_out[115]
  PIN rw0_rd_out[116]
    DIRECTION OUTPUT ;
    USE SIGNAL ;
    SHAPE ABUTMENT ;
    PORT
      LAYER M3 ;
      RECT 123.183 0.000 123.201 0.054 ;
    END
  END rw0_rd_out[116]
  PIN rw0_rd_out[117]
    DIRECTION OUTPUT ;
    USE SIGNAL ;
    SHAPE ABUTMENT ;
    PORT
      LAYER M3 ;
      RECT 123.687 0.000 123.705 0.054 ;
    END
  END rw0_rd_out[117]
  PIN rw0_rd_out[118]
    DIRECTION OUTPUT ;
    USE SIGNAL ;
    SHAPE ABUTMENT ;
    PORT
      LAYER M3 ;
      RECT 124.191 0.000 124.209 0.054 ;
    END
  END rw0_rd_out[118]
  PIN rw0_rd_out[119]
    DIRECTION OUTPUT ;
    USE SIGNAL ;
    SHAPE ABUTMENT ;
    PORT
      LAYER M3 ;
      RECT 124.695 0.000 124.713 0.054 ;
    END
  END rw0_rd_out[119]
  PIN rw0_rd_out[120]
    DIRECTION OUTPUT ;
    USE SIGNAL ;
    SHAPE ABUTMENT ;
    PORT
      LAYER M3 ;
      RECT 125.199 0.000 125.217 0.054 ;
    END
  END rw0_rd_out[120]
  PIN rw0_rd_out[121]
    DIRECTION OUTPUT ;
    USE SIGNAL ;
    SHAPE ABUTMENT ;
    PORT
      LAYER M3 ;
      RECT 125.703 0.000 125.721 0.054 ;
    END
  END rw0_rd_out[121]
  PIN rw0_rd_out[122]
    DIRECTION OUTPUT ;
    USE SIGNAL ;
    SHAPE ABUTMENT ;
    PORT
      LAYER M3 ;
      RECT 126.207 0.000 126.225 0.054 ;
    END
  END rw0_rd_out[122]
  PIN rw0_rd_out[123]
    DIRECTION OUTPUT ;
    USE SIGNAL ;
    SHAPE ABUTMENT ;
    PORT
      LAYER M3 ;
      RECT 126.711 0.000 126.729 0.054 ;
    END
  END rw0_rd_out[123]
  PIN rw0_rd_out[124]
    DIRECTION OUTPUT ;
    USE SIGNAL ;
    SHAPE ABUTMENT ;
    PORT
      LAYER M3 ;
      RECT 127.215 0.000 127.233 0.054 ;
    END
  END rw0_rd_out[124]
  PIN rw0_rd_out[125]
    DIRECTION OUTPUT ;
    USE SIGNAL ;
    SHAPE ABUTMENT ;
    PORT
      LAYER M3 ;
      RECT 127.719 0.000 127.737 0.054 ;
    END
  END rw0_rd_out[125]
  PIN rw0_rd_out[126]
    DIRECTION OUTPUT ;
    USE SIGNAL ;
    SHAPE ABUTMENT ;
    PORT
      LAYER M3 ;
      RECT 128.223 0.000 128.241 0.054 ;
    END
  END rw0_rd_out[126]
  PIN rw0_rd_out[127]
    DIRECTION OUTPUT ;
    USE SIGNAL ;
    SHAPE ABUTMENT ;
    PORT
      LAYER M3 ;
      RECT 128.727 0.000 128.745 0.054 ;
    END
  END rw0_rd_out[127]
  PIN rw0_rd_out[128]
    DIRECTION OUTPUT ;
    USE SIGNAL ;
    SHAPE ABUTMENT ;
    PORT
      LAYER M3 ;
      RECT 0.207 86.746 0.225 86.800 ;
    END
  END rw0_rd_out[128]
  PIN rw0_rd_out[129]
    DIRECTION OUTPUT ;
    USE SIGNAL ;
    SHAPE ABUTMENT ;
    PORT
      LAYER M3 ;
      RECT 1.251 86.746 1.269 86.800 ;
    END
  END rw0_rd_out[129]
  PIN rw0_rd_out[130]
    DIRECTION OUTPUT ;
    USE SIGNAL ;
    SHAPE ABUTMENT ;
    PORT
      LAYER M3 ;
      RECT 2.295 86.746 2.313 86.800 ;
    END
  END rw0_rd_out[130]
  PIN rw0_rd_out[131]
    DIRECTION OUTPUT ;
    USE SIGNAL ;
    SHAPE ABUTMENT ;
    PORT
      LAYER M3 ;
      RECT 3.339 86.746 3.357 86.800 ;
    END
  END rw0_rd_out[131]
  PIN rw0_rd_out[132]
    DIRECTION OUTPUT ;
    USE SIGNAL ;
    SHAPE ABUTMENT ;
    PORT
      LAYER M3 ;
      RECT 4.383 86.746 4.401 86.800 ;
    END
  END rw0_rd_out[132]
  PIN rw0_rd_out[133]
    DIRECTION OUTPUT ;
    USE SIGNAL ;
    SHAPE ABUTMENT ;
    PORT
      LAYER M3 ;
      RECT 5.427 86.746 5.445 86.800 ;
    END
  END rw0_rd_out[133]
  PIN rw0_rd_out[134]
    DIRECTION OUTPUT ;
    USE SIGNAL ;
    SHAPE ABUTMENT ;
    PORT
      LAYER M3 ;
      RECT 6.471 86.746 6.489 86.800 ;
    END
  END rw0_rd_out[134]
  PIN rw0_rd_out[135]
    DIRECTION OUTPUT ;
    USE SIGNAL ;
    SHAPE ABUTMENT ;
    PORT
      LAYER M3 ;
      RECT 7.515 86.746 7.533 86.800 ;
    END
  END rw0_rd_out[135]
  PIN rw0_rd_out[136]
    DIRECTION OUTPUT ;
    USE SIGNAL ;
    SHAPE ABUTMENT ;
    PORT
      LAYER M3 ;
      RECT 8.559 86.746 8.577 86.800 ;
    END
  END rw0_rd_out[136]
  PIN rw0_rd_out[137]
    DIRECTION OUTPUT ;
    USE SIGNAL ;
    SHAPE ABUTMENT ;
    PORT
      LAYER M3 ;
      RECT 9.603 86.746 9.621 86.800 ;
    END
  END rw0_rd_out[137]
  PIN rw0_rd_out[138]
    DIRECTION OUTPUT ;
    USE SIGNAL ;
    SHAPE ABUTMENT ;
    PORT
      LAYER M3 ;
      RECT 10.647 86.746 10.665 86.800 ;
    END
  END rw0_rd_out[138]
  PIN rw0_rd_out[139]
    DIRECTION OUTPUT ;
    USE SIGNAL ;
    SHAPE ABUTMENT ;
    PORT
      LAYER M3 ;
      RECT 11.691 86.746 11.709 86.800 ;
    END
  END rw0_rd_out[139]
  PIN rw0_rd_out[140]
    DIRECTION OUTPUT ;
    USE SIGNAL ;
    SHAPE ABUTMENT ;
    PORT
      LAYER M3 ;
      RECT 12.735 86.746 12.753 86.800 ;
    END
  END rw0_rd_out[140]
  PIN rw0_rd_out[141]
    DIRECTION OUTPUT ;
    USE SIGNAL ;
    SHAPE ABUTMENT ;
    PORT
      LAYER M3 ;
      RECT 13.779 86.746 13.797 86.800 ;
    END
  END rw0_rd_out[141]
  PIN rw0_rd_out[142]
    DIRECTION OUTPUT ;
    USE SIGNAL ;
    SHAPE ABUTMENT ;
    PORT
      LAYER M3 ;
      RECT 14.823 86.746 14.841 86.800 ;
    END
  END rw0_rd_out[142]
  PIN rw0_rd_out[143]
    DIRECTION OUTPUT ;
    USE SIGNAL ;
    SHAPE ABUTMENT ;
    PORT
      LAYER M3 ;
      RECT 15.867 86.746 15.885 86.800 ;
    END
  END rw0_rd_out[143]
  PIN rw0_rd_out[144]
    DIRECTION OUTPUT ;
    USE SIGNAL ;
    SHAPE ABUTMENT ;
    PORT
      LAYER M3 ;
      RECT 16.911 86.746 16.929 86.800 ;
    END
  END rw0_rd_out[144]
  PIN rw0_rd_out[145]
    DIRECTION OUTPUT ;
    USE SIGNAL ;
    SHAPE ABUTMENT ;
    PORT
      LAYER M3 ;
      RECT 17.955 86.746 17.973 86.800 ;
    END
  END rw0_rd_out[145]
  PIN rw0_rd_out[146]
    DIRECTION OUTPUT ;
    USE SIGNAL ;
    SHAPE ABUTMENT ;
    PORT
      LAYER M3 ;
      RECT 18.999 86.746 19.017 86.800 ;
    END
  END rw0_rd_out[146]
  PIN rw0_rd_out[147]
    DIRECTION OUTPUT ;
    USE SIGNAL ;
    SHAPE ABUTMENT ;
    PORT
      LAYER M3 ;
      RECT 20.043 86.746 20.061 86.800 ;
    END
  END rw0_rd_out[147]
  PIN rw0_rd_out[148]
    DIRECTION OUTPUT ;
    USE SIGNAL ;
    SHAPE ABUTMENT ;
    PORT
      LAYER M3 ;
      RECT 21.087 86.746 21.105 86.800 ;
    END
  END rw0_rd_out[148]
  PIN rw0_rd_out[149]
    DIRECTION OUTPUT ;
    USE SIGNAL ;
    SHAPE ABUTMENT ;
    PORT
      LAYER M3 ;
      RECT 22.131 86.746 22.149 86.800 ;
    END
  END rw0_rd_out[149]
  PIN rw0_rd_out[150]
    DIRECTION OUTPUT ;
    USE SIGNAL ;
    SHAPE ABUTMENT ;
    PORT
      LAYER M3 ;
      RECT 23.175 86.746 23.193 86.800 ;
    END
  END rw0_rd_out[150]
  PIN rw0_rd_out[151]
    DIRECTION OUTPUT ;
    USE SIGNAL ;
    SHAPE ABUTMENT ;
    PORT
      LAYER M3 ;
      RECT 24.219 86.746 24.237 86.800 ;
    END
  END rw0_rd_out[151]
  PIN rw0_rd_out[152]
    DIRECTION OUTPUT ;
    USE SIGNAL ;
    SHAPE ABUTMENT ;
    PORT
      LAYER M3 ;
      RECT 25.263 86.746 25.281 86.800 ;
    END
  END rw0_rd_out[152]
  PIN rw0_rd_out[153]
    DIRECTION OUTPUT ;
    USE SIGNAL ;
    SHAPE ABUTMENT ;
    PORT
      LAYER M3 ;
      RECT 26.307 86.746 26.325 86.800 ;
    END
  END rw0_rd_out[153]
  PIN rw0_rd_out[154]
    DIRECTION OUTPUT ;
    USE SIGNAL ;
    SHAPE ABUTMENT ;
    PORT
      LAYER M3 ;
      RECT 27.351 86.746 27.369 86.800 ;
    END
  END rw0_rd_out[154]
  PIN rw0_rd_out[155]
    DIRECTION OUTPUT ;
    USE SIGNAL ;
    SHAPE ABUTMENT ;
    PORT
      LAYER M3 ;
      RECT 28.395 86.746 28.413 86.800 ;
    END
  END rw0_rd_out[155]
  PIN rw0_rd_out[156]
    DIRECTION OUTPUT ;
    USE SIGNAL ;
    SHAPE ABUTMENT ;
    PORT
      LAYER M3 ;
      RECT 29.439 86.746 29.457 86.800 ;
    END
  END rw0_rd_out[156]
  PIN rw0_rd_out[157]
    DIRECTION OUTPUT ;
    USE SIGNAL ;
    SHAPE ABUTMENT ;
    PORT
      LAYER M3 ;
      RECT 30.483 86.746 30.501 86.800 ;
    END
  END rw0_rd_out[157]
  PIN rw0_rd_out[158]
    DIRECTION OUTPUT ;
    USE SIGNAL ;
    SHAPE ABUTMENT ;
    PORT
      LAYER M3 ;
      RECT 31.527 86.746 31.545 86.800 ;
    END
  END rw0_rd_out[158]
  PIN rw0_rd_out[159]
    DIRECTION OUTPUT ;
    USE SIGNAL ;
    SHAPE ABUTMENT ;
    PORT
      LAYER M3 ;
      RECT 32.571 86.746 32.589 86.800 ;
    END
  END rw0_rd_out[159]
  PIN rw0_rd_out[160]
    DIRECTION OUTPUT ;
    USE SIGNAL ;
    SHAPE ABUTMENT ;
    PORT
      LAYER M3 ;
      RECT 33.615 86.746 33.633 86.800 ;
    END
  END rw0_rd_out[160]
  PIN rw0_rd_out[161]
    DIRECTION OUTPUT ;
    USE SIGNAL ;
    SHAPE ABUTMENT ;
    PORT
      LAYER M3 ;
      RECT 34.659 86.746 34.677 86.800 ;
    END
  END rw0_rd_out[161]
  PIN rw0_rd_out[162]
    DIRECTION OUTPUT ;
    USE SIGNAL ;
    SHAPE ABUTMENT ;
    PORT
      LAYER M3 ;
      RECT 35.703 86.746 35.721 86.800 ;
    END
  END rw0_rd_out[162]
  PIN rw0_rd_out[163]
    DIRECTION OUTPUT ;
    USE SIGNAL ;
    SHAPE ABUTMENT ;
    PORT
      LAYER M3 ;
      RECT 36.747 86.746 36.765 86.800 ;
    END
  END rw0_rd_out[163]
  PIN rw0_rd_out[164]
    DIRECTION OUTPUT ;
    USE SIGNAL ;
    SHAPE ABUTMENT ;
    PORT
      LAYER M3 ;
      RECT 37.791 86.746 37.809 86.800 ;
    END
  END rw0_rd_out[164]
  PIN rw0_rd_out[165]
    DIRECTION OUTPUT ;
    USE SIGNAL ;
    SHAPE ABUTMENT ;
    PORT
      LAYER M3 ;
      RECT 38.835 86.746 38.853 86.800 ;
    END
  END rw0_rd_out[165]
  PIN rw0_rd_out[166]
    DIRECTION OUTPUT ;
    USE SIGNAL ;
    SHAPE ABUTMENT ;
    PORT
      LAYER M3 ;
      RECT 39.879 86.746 39.897 86.800 ;
    END
  END rw0_rd_out[166]
  PIN rw0_rd_out[167]
    DIRECTION OUTPUT ;
    USE SIGNAL ;
    SHAPE ABUTMENT ;
    PORT
      LAYER M3 ;
      RECT 40.923 86.746 40.941 86.800 ;
    END
  END rw0_rd_out[167]
  PIN rw0_rd_out[168]
    DIRECTION OUTPUT ;
    USE SIGNAL ;
    SHAPE ABUTMENT ;
    PORT
      LAYER M3 ;
      RECT 41.967 86.746 41.985 86.800 ;
    END
  END rw0_rd_out[168]
  PIN rw0_rd_out[169]
    DIRECTION OUTPUT ;
    USE SIGNAL ;
    SHAPE ABUTMENT ;
    PORT
      LAYER M3 ;
      RECT 43.011 86.746 43.029 86.800 ;
    END
  END rw0_rd_out[169]
  PIN rw0_rd_out[170]
    DIRECTION OUTPUT ;
    USE SIGNAL ;
    SHAPE ABUTMENT ;
    PORT
      LAYER M3 ;
      RECT 44.055 86.746 44.073 86.800 ;
    END
  END rw0_rd_out[170]
  PIN rw0_rd_out[171]
    DIRECTION OUTPUT ;
    USE SIGNAL ;
    SHAPE ABUTMENT ;
    PORT
      LAYER M3 ;
      RECT 45.099 86.746 45.117 86.800 ;
    END
  END rw0_rd_out[171]
  PIN rw0_rd_out[172]
    DIRECTION OUTPUT ;
    USE SIGNAL ;
    SHAPE ABUTMENT ;
    PORT
      LAYER M3 ;
      RECT 46.143 86.746 46.161 86.800 ;
    END
  END rw0_rd_out[172]
  PIN rw0_rd_out[173]
    DIRECTION OUTPUT ;
    USE SIGNAL ;
    SHAPE ABUTMENT ;
    PORT
      LAYER M3 ;
      RECT 47.187 86.746 47.205 86.800 ;
    END
  END rw0_rd_out[173]
  PIN rw0_rd_out[174]
    DIRECTION OUTPUT ;
    USE SIGNAL ;
    SHAPE ABUTMENT ;
    PORT
      LAYER M3 ;
      RECT 48.231 86.746 48.249 86.800 ;
    END
  END rw0_rd_out[174]
  PIN rw0_rd_out[175]
    DIRECTION OUTPUT ;
    USE SIGNAL ;
    SHAPE ABUTMENT ;
    PORT
      LAYER M3 ;
      RECT 49.275 86.746 49.293 86.800 ;
    END
  END rw0_rd_out[175]
  PIN rw0_rd_out[176]
    DIRECTION OUTPUT ;
    USE SIGNAL ;
    SHAPE ABUTMENT ;
    PORT
      LAYER M3 ;
      RECT 50.319 86.746 50.337 86.800 ;
    END
  END rw0_rd_out[176]
  PIN rw0_rd_out[177]
    DIRECTION OUTPUT ;
    USE SIGNAL ;
    SHAPE ABUTMENT ;
    PORT
      LAYER M3 ;
      RECT 51.363 86.746 51.381 86.800 ;
    END
  END rw0_rd_out[177]
  PIN rw0_rd_out[178]
    DIRECTION OUTPUT ;
    USE SIGNAL ;
    SHAPE ABUTMENT ;
    PORT
      LAYER M3 ;
      RECT 52.407 86.746 52.425 86.800 ;
    END
  END rw0_rd_out[178]
  PIN rw0_rd_out[179]
    DIRECTION OUTPUT ;
    USE SIGNAL ;
    SHAPE ABUTMENT ;
    PORT
      LAYER M3 ;
      RECT 53.451 86.746 53.469 86.800 ;
    END
  END rw0_rd_out[179]
  PIN rw0_rd_out[180]
    DIRECTION OUTPUT ;
    USE SIGNAL ;
    SHAPE ABUTMENT ;
    PORT
      LAYER M3 ;
      RECT 54.495 86.746 54.513 86.800 ;
    END
  END rw0_rd_out[180]
  PIN rw0_rd_out[181]
    DIRECTION OUTPUT ;
    USE SIGNAL ;
    SHAPE ABUTMENT ;
    PORT
      LAYER M3 ;
      RECT 55.539 86.746 55.557 86.800 ;
    END
  END rw0_rd_out[181]
  PIN rw0_rd_out[182]
    DIRECTION OUTPUT ;
    USE SIGNAL ;
    SHAPE ABUTMENT ;
    PORT
      LAYER M3 ;
      RECT 56.583 86.746 56.601 86.800 ;
    END
  END rw0_rd_out[182]
  PIN rw0_rd_out[183]
    DIRECTION OUTPUT ;
    USE SIGNAL ;
    SHAPE ABUTMENT ;
    PORT
      LAYER M3 ;
      RECT 57.627 86.746 57.645 86.800 ;
    END
  END rw0_rd_out[183]
  PIN rw0_rd_out[184]
    DIRECTION OUTPUT ;
    USE SIGNAL ;
    SHAPE ABUTMENT ;
    PORT
      LAYER M3 ;
      RECT 58.671 86.746 58.689 86.800 ;
    END
  END rw0_rd_out[184]
  PIN rw0_rd_out[185]
    DIRECTION OUTPUT ;
    USE SIGNAL ;
    SHAPE ABUTMENT ;
    PORT
      LAYER M3 ;
      RECT 59.715 86.746 59.733 86.800 ;
    END
  END rw0_rd_out[185]
  PIN rw0_rd_out[186]
    DIRECTION OUTPUT ;
    USE SIGNAL ;
    SHAPE ABUTMENT ;
    PORT
      LAYER M3 ;
      RECT 60.759 86.746 60.777 86.800 ;
    END
  END rw0_rd_out[186]
  PIN rw0_rd_out[187]
    DIRECTION OUTPUT ;
    USE SIGNAL ;
    SHAPE ABUTMENT ;
    PORT
      LAYER M3 ;
      RECT 61.803 86.746 61.821 86.800 ;
    END
  END rw0_rd_out[187]
  PIN rw0_rd_out[188]
    DIRECTION OUTPUT ;
    USE SIGNAL ;
    SHAPE ABUTMENT ;
    PORT
      LAYER M3 ;
      RECT 62.847 86.746 62.865 86.800 ;
    END
  END rw0_rd_out[188]
  PIN rw0_rd_out[189]
    DIRECTION OUTPUT ;
    USE SIGNAL ;
    SHAPE ABUTMENT ;
    PORT
      LAYER M3 ;
      RECT 63.891 86.746 63.909 86.800 ;
    END
  END rw0_rd_out[189]
  PIN rw0_rd_out[190]
    DIRECTION OUTPUT ;
    USE SIGNAL ;
    SHAPE ABUTMENT ;
    PORT
      LAYER M3 ;
      RECT 64.935 86.746 64.953 86.800 ;
    END
  END rw0_rd_out[190]
  PIN rw0_rd_out[191]
    DIRECTION OUTPUT ;
    USE SIGNAL ;
    SHAPE ABUTMENT ;
    PORT
      LAYER M3 ;
      RECT 65.979 86.746 65.997 86.800 ;
    END
  END rw0_rd_out[191]
  PIN rw0_rd_out[192]
    DIRECTION OUTPUT ;
    USE SIGNAL ;
    SHAPE ABUTMENT ;
    PORT
      LAYER M3 ;
      RECT 67.023 86.746 67.041 86.800 ;
    END
  END rw0_rd_out[192]
  PIN rw0_rd_out[193]
    DIRECTION OUTPUT ;
    USE SIGNAL ;
    SHAPE ABUTMENT ;
    PORT
      LAYER M3 ;
      RECT 68.067 86.746 68.085 86.800 ;
    END
  END rw0_rd_out[193]
  PIN rw0_rd_out[194]
    DIRECTION OUTPUT ;
    USE SIGNAL ;
    SHAPE ABUTMENT ;
    PORT
      LAYER M3 ;
      RECT 69.111 86.746 69.129 86.800 ;
    END
  END rw0_rd_out[194]
  PIN rw0_rd_out[195]
    DIRECTION OUTPUT ;
    USE SIGNAL ;
    SHAPE ABUTMENT ;
    PORT
      LAYER M3 ;
      RECT 70.155 86.746 70.173 86.800 ;
    END
  END rw0_rd_out[195]
  PIN rw0_rd_out[196]
    DIRECTION OUTPUT ;
    USE SIGNAL ;
    SHAPE ABUTMENT ;
    PORT
      LAYER M3 ;
      RECT 71.199 86.746 71.217 86.800 ;
    END
  END rw0_rd_out[196]
  PIN rw0_rd_out[197]
    DIRECTION OUTPUT ;
    USE SIGNAL ;
    SHAPE ABUTMENT ;
    PORT
      LAYER M3 ;
      RECT 72.243 86.746 72.261 86.800 ;
    END
  END rw0_rd_out[197]
  PIN rw0_rd_out[198]
    DIRECTION OUTPUT ;
    USE SIGNAL ;
    SHAPE ABUTMENT ;
    PORT
      LAYER M3 ;
      RECT 73.287 86.746 73.305 86.800 ;
    END
  END rw0_rd_out[198]
  PIN rw0_rd_out[199]
    DIRECTION OUTPUT ;
    USE SIGNAL ;
    SHAPE ABUTMENT ;
    PORT
      LAYER M3 ;
      RECT 74.331 86.746 74.349 86.800 ;
    END
  END rw0_rd_out[199]
  PIN rw0_rd_out[200]
    DIRECTION OUTPUT ;
    USE SIGNAL ;
    SHAPE ABUTMENT ;
    PORT
      LAYER M3 ;
      RECT 75.375 86.746 75.393 86.800 ;
    END
  END rw0_rd_out[200]
  PIN rw0_rd_out[201]
    DIRECTION OUTPUT ;
    USE SIGNAL ;
    SHAPE ABUTMENT ;
    PORT
      LAYER M3 ;
      RECT 76.419 86.746 76.437 86.800 ;
    END
  END rw0_rd_out[201]
  PIN rw0_rd_out[202]
    DIRECTION OUTPUT ;
    USE SIGNAL ;
    SHAPE ABUTMENT ;
    PORT
      LAYER M3 ;
      RECT 77.463 86.746 77.481 86.800 ;
    END
  END rw0_rd_out[202]
  PIN rw0_rd_out[203]
    DIRECTION OUTPUT ;
    USE SIGNAL ;
    SHAPE ABUTMENT ;
    PORT
      LAYER M3 ;
      RECT 78.507 86.746 78.525 86.800 ;
    END
  END rw0_rd_out[203]
  PIN rw0_rd_out[204]
    DIRECTION OUTPUT ;
    USE SIGNAL ;
    SHAPE ABUTMENT ;
    PORT
      LAYER M3 ;
      RECT 79.551 86.746 79.569 86.800 ;
    END
  END rw0_rd_out[204]
  PIN rw0_rd_out[205]
    DIRECTION OUTPUT ;
    USE SIGNAL ;
    SHAPE ABUTMENT ;
    PORT
      LAYER M3 ;
      RECT 80.595 86.746 80.613 86.800 ;
    END
  END rw0_rd_out[205]
  PIN rw0_rd_out[206]
    DIRECTION OUTPUT ;
    USE SIGNAL ;
    SHAPE ABUTMENT ;
    PORT
      LAYER M3 ;
      RECT 81.639 86.746 81.657 86.800 ;
    END
  END rw0_rd_out[206]
  PIN rw0_rd_out[207]
    DIRECTION OUTPUT ;
    USE SIGNAL ;
    SHAPE ABUTMENT ;
    PORT
      LAYER M3 ;
      RECT 82.683 86.746 82.701 86.800 ;
    END
  END rw0_rd_out[207]
  PIN rw0_rd_out[208]
    DIRECTION OUTPUT ;
    USE SIGNAL ;
    SHAPE ABUTMENT ;
    PORT
      LAYER M3 ;
      RECT 83.727 86.746 83.745 86.800 ;
    END
  END rw0_rd_out[208]
  PIN rw0_rd_out[209]
    DIRECTION OUTPUT ;
    USE SIGNAL ;
    SHAPE ABUTMENT ;
    PORT
      LAYER M3 ;
      RECT 84.771 86.746 84.789 86.800 ;
    END
  END rw0_rd_out[209]
  PIN rw0_rd_out[210]
    DIRECTION OUTPUT ;
    USE SIGNAL ;
    SHAPE ABUTMENT ;
    PORT
      LAYER M3 ;
      RECT 85.815 86.746 85.833 86.800 ;
    END
  END rw0_rd_out[210]
  PIN rw0_rd_out[211]
    DIRECTION OUTPUT ;
    USE SIGNAL ;
    SHAPE ABUTMENT ;
    PORT
      LAYER M3 ;
      RECT 86.859 86.746 86.877 86.800 ;
    END
  END rw0_rd_out[211]
  PIN rw0_rd_out[212]
    DIRECTION OUTPUT ;
    USE SIGNAL ;
    SHAPE ABUTMENT ;
    PORT
      LAYER M3 ;
      RECT 87.903 86.746 87.921 86.800 ;
    END
  END rw0_rd_out[212]
  PIN rw0_rd_out[213]
    DIRECTION OUTPUT ;
    USE SIGNAL ;
    SHAPE ABUTMENT ;
    PORT
      LAYER M3 ;
      RECT 88.947 86.746 88.965 86.800 ;
    END
  END rw0_rd_out[213]
  PIN rw0_rd_out[214]
    DIRECTION OUTPUT ;
    USE SIGNAL ;
    SHAPE ABUTMENT ;
    PORT
      LAYER M3 ;
      RECT 89.991 86.746 90.009 86.800 ;
    END
  END rw0_rd_out[214]
  PIN rw0_rd_out[215]
    DIRECTION OUTPUT ;
    USE SIGNAL ;
    SHAPE ABUTMENT ;
    PORT
      LAYER M3 ;
      RECT 91.035 86.746 91.053 86.800 ;
    END
  END rw0_rd_out[215]
  PIN rw0_rd_out[216]
    DIRECTION OUTPUT ;
    USE SIGNAL ;
    SHAPE ABUTMENT ;
    PORT
      LAYER M3 ;
      RECT 92.079 86.746 92.097 86.800 ;
    END
  END rw0_rd_out[216]
  PIN rw0_rd_out[217]
    DIRECTION OUTPUT ;
    USE SIGNAL ;
    SHAPE ABUTMENT ;
    PORT
      LAYER M3 ;
      RECT 93.123 86.746 93.141 86.800 ;
    END
  END rw0_rd_out[217]
  PIN rw0_rd_out[218]
    DIRECTION OUTPUT ;
    USE SIGNAL ;
    SHAPE ABUTMENT ;
    PORT
      LAYER M3 ;
      RECT 94.167 86.746 94.185 86.800 ;
    END
  END rw0_rd_out[218]
  PIN rw0_rd_out[219]
    DIRECTION OUTPUT ;
    USE SIGNAL ;
    SHAPE ABUTMENT ;
    PORT
      LAYER M3 ;
      RECT 95.211 86.746 95.229 86.800 ;
    END
  END rw0_rd_out[219]
  PIN rw0_rd_out[220]
    DIRECTION OUTPUT ;
    USE SIGNAL ;
    SHAPE ABUTMENT ;
    PORT
      LAYER M3 ;
      RECT 96.255 86.746 96.273 86.800 ;
    END
  END rw0_rd_out[220]
  PIN rw0_rd_out[221]
    DIRECTION OUTPUT ;
    USE SIGNAL ;
    SHAPE ABUTMENT ;
    PORT
      LAYER M3 ;
      RECT 97.299 86.746 97.317 86.800 ;
    END
  END rw0_rd_out[221]
  PIN rw0_rd_out[222]
    DIRECTION OUTPUT ;
    USE SIGNAL ;
    SHAPE ABUTMENT ;
    PORT
      LAYER M3 ;
      RECT 98.343 86.746 98.361 86.800 ;
    END
  END rw0_rd_out[222]
  PIN rw0_rd_out[223]
    DIRECTION OUTPUT ;
    USE SIGNAL ;
    SHAPE ABUTMENT ;
    PORT
      LAYER M3 ;
      RECT 99.387 86.746 99.405 86.800 ;
    END
  END rw0_rd_out[223]
  PIN rw0_rd_out[224]
    DIRECTION OUTPUT ;
    USE SIGNAL ;
    SHAPE ABUTMENT ;
    PORT
      LAYER M3 ;
      RECT 100.431 86.746 100.449 86.800 ;
    END
  END rw0_rd_out[224]
  PIN rw0_rd_out[225]
    DIRECTION OUTPUT ;
    USE SIGNAL ;
    SHAPE ABUTMENT ;
    PORT
      LAYER M3 ;
      RECT 101.475 86.746 101.493 86.800 ;
    END
  END rw0_rd_out[225]
  PIN rw0_rd_out[226]
    DIRECTION OUTPUT ;
    USE SIGNAL ;
    SHAPE ABUTMENT ;
    PORT
      LAYER M3 ;
      RECT 102.519 86.746 102.537 86.800 ;
    END
  END rw0_rd_out[226]
  PIN rw0_rd_out[227]
    DIRECTION OUTPUT ;
    USE SIGNAL ;
    SHAPE ABUTMENT ;
    PORT
      LAYER M3 ;
      RECT 103.563 86.746 103.581 86.800 ;
    END
  END rw0_rd_out[227]
  PIN rw0_rd_out[228]
    DIRECTION OUTPUT ;
    USE SIGNAL ;
    SHAPE ABUTMENT ;
    PORT
      LAYER M3 ;
      RECT 104.607 86.746 104.625 86.800 ;
    END
  END rw0_rd_out[228]
  PIN rw0_rd_out[229]
    DIRECTION OUTPUT ;
    USE SIGNAL ;
    SHAPE ABUTMENT ;
    PORT
      LAYER M3 ;
      RECT 105.651 86.746 105.669 86.800 ;
    END
  END rw0_rd_out[229]
  PIN rw0_rd_out[230]
    DIRECTION OUTPUT ;
    USE SIGNAL ;
    SHAPE ABUTMENT ;
    PORT
      LAYER M3 ;
      RECT 106.695 86.746 106.713 86.800 ;
    END
  END rw0_rd_out[230]
  PIN rw0_rd_out[231]
    DIRECTION OUTPUT ;
    USE SIGNAL ;
    SHAPE ABUTMENT ;
    PORT
      LAYER M3 ;
      RECT 107.739 86.746 107.757 86.800 ;
    END
  END rw0_rd_out[231]
  PIN rw0_rd_out[232]
    DIRECTION OUTPUT ;
    USE SIGNAL ;
    SHAPE ABUTMENT ;
    PORT
      LAYER M3 ;
      RECT 108.783 86.746 108.801 86.800 ;
    END
  END rw0_rd_out[232]
  PIN rw0_rd_out[233]
    DIRECTION OUTPUT ;
    USE SIGNAL ;
    SHAPE ABUTMENT ;
    PORT
      LAYER M3 ;
      RECT 109.827 86.746 109.845 86.800 ;
    END
  END rw0_rd_out[233]
  PIN rw0_rd_out[234]
    DIRECTION OUTPUT ;
    USE SIGNAL ;
    SHAPE ABUTMENT ;
    PORT
      LAYER M3 ;
      RECT 110.871 86.746 110.889 86.800 ;
    END
  END rw0_rd_out[234]
  PIN rw0_rd_out[235]
    DIRECTION OUTPUT ;
    USE SIGNAL ;
    SHAPE ABUTMENT ;
    PORT
      LAYER M3 ;
      RECT 111.915 86.746 111.933 86.800 ;
    END
  END rw0_rd_out[235]
  PIN rw0_rd_out[236]
    DIRECTION OUTPUT ;
    USE SIGNAL ;
    SHAPE ABUTMENT ;
    PORT
      LAYER M3 ;
      RECT 112.959 86.746 112.977 86.800 ;
    END
  END rw0_rd_out[236]
  PIN rw0_rd_out[237]
    DIRECTION OUTPUT ;
    USE SIGNAL ;
    SHAPE ABUTMENT ;
    PORT
      LAYER M3 ;
      RECT 114.003 86.746 114.021 86.800 ;
    END
  END rw0_rd_out[237]
  PIN rw0_rd_out[238]
    DIRECTION OUTPUT ;
    USE SIGNAL ;
    SHAPE ABUTMENT ;
    PORT
      LAYER M3 ;
      RECT 115.047 86.746 115.065 86.800 ;
    END
  END rw0_rd_out[238]
  PIN rw0_rd_out[239]
    DIRECTION OUTPUT ;
    USE SIGNAL ;
    SHAPE ABUTMENT ;
    PORT
      LAYER M3 ;
      RECT 116.091 86.746 116.109 86.800 ;
    END
  END rw0_rd_out[239]
  PIN rw0_rd_out[240]
    DIRECTION OUTPUT ;
    USE SIGNAL ;
    SHAPE ABUTMENT ;
    PORT
      LAYER M3 ;
      RECT 117.135 86.746 117.153 86.800 ;
    END
  END rw0_rd_out[240]
  PIN rw0_rd_out[241]
    DIRECTION OUTPUT ;
    USE SIGNAL ;
    SHAPE ABUTMENT ;
    PORT
      LAYER M3 ;
      RECT 118.179 86.746 118.197 86.800 ;
    END
  END rw0_rd_out[241]
  PIN rw0_rd_out[242]
    DIRECTION OUTPUT ;
    USE SIGNAL ;
    SHAPE ABUTMENT ;
    PORT
      LAYER M3 ;
      RECT 119.223 86.746 119.241 86.800 ;
    END
  END rw0_rd_out[242]
  PIN rw0_rd_out[243]
    DIRECTION OUTPUT ;
    USE SIGNAL ;
    SHAPE ABUTMENT ;
    PORT
      LAYER M3 ;
      RECT 120.267 86.746 120.285 86.800 ;
    END
  END rw0_rd_out[243]
  PIN rw0_rd_out[244]
    DIRECTION OUTPUT ;
    USE SIGNAL ;
    SHAPE ABUTMENT ;
    PORT
      LAYER M3 ;
      RECT 121.311 86.746 121.329 86.800 ;
    END
  END rw0_rd_out[244]
  PIN rw0_rd_out[245]
    DIRECTION OUTPUT ;
    USE SIGNAL ;
    SHAPE ABUTMENT ;
    PORT
      LAYER M3 ;
      RECT 122.355 86.746 122.373 86.800 ;
    END
  END rw0_rd_out[245]
  PIN rw0_rd_out[246]
    DIRECTION OUTPUT ;
    USE SIGNAL ;
    SHAPE ABUTMENT ;
    PORT
      LAYER M3 ;
      RECT 123.399 86.746 123.417 86.800 ;
    END
  END rw0_rd_out[246]
  PIN rw0_rd_out[247]
    DIRECTION OUTPUT ;
    USE SIGNAL ;
    SHAPE ABUTMENT ;
    PORT
      LAYER M3 ;
      RECT 124.443 86.746 124.461 86.800 ;
    END
  END rw0_rd_out[247]
  PIN rw0_rd_out[248]
    DIRECTION OUTPUT ;
    USE SIGNAL ;
    SHAPE ABUTMENT ;
    PORT
      LAYER M3 ;
      RECT 125.487 86.746 125.505 86.800 ;
    END
  END rw0_rd_out[248]
  PIN rw0_rd_out[249]
    DIRECTION OUTPUT ;
    USE SIGNAL ;
    SHAPE ABUTMENT ;
    PORT
      LAYER M3 ;
      RECT 126.531 86.746 126.549 86.800 ;
    END
  END rw0_rd_out[249]
  PIN rw0_rd_out[250]
    DIRECTION OUTPUT ;
    USE SIGNAL ;
    SHAPE ABUTMENT ;
    PORT
      LAYER M3 ;
      RECT 127.575 86.746 127.593 86.800 ;
    END
  END rw0_rd_out[250]
  PIN rw0_rd_out[251]
    DIRECTION OUTPUT ;
    USE SIGNAL ;
    SHAPE ABUTMENT ;
    PORT
      LAYER M3 ;
      RECT 128.619 86.746 128.637 86.800 ;
    END
  END rw0_rd_out[251]
  PIN rw0_rd_out[252]
    DIRECTION OUTPUT ;
    USE SIGNAL ;
    SHAPE ABUTMENT ;
    PORT
      LAYER M3 ;
      RECT 129.663 86.746 129.681 86.800 ;
    END
  END rw0_rd_out[252]
  PIN rw0_rd_out[253]
    DIRECTION OUTPUT ;
    USE SIGNAL ;
    SHAPE ABUTMENT ;
    PORT
      LAYER M3 ;
      RECT 130.707 86.746 130.725 86.800 ;
    END
  END rw0_rd_out[253]
  PIN rw0_rd_out[254]
    DIRECTION OUTPUT ;
    USE SIGNAL ;
    SHAPE ABUTMENT ;
    PORT
      LAYER M3 ;
      RECT 131.751 86.746 131.769 86.800 ;
    END
  END rw0_rd_out[254]
  PIN rw0_rd_out[255]
    DIRECTION OUTPUT ;
    USE SIGNAL ;
    SHAPE ABUTMENT ;
    PORT
      LAYER M3 ;
      RECT 132.795 86.746 132.813 86.800 ;
    END
  END rw0_rd_out[255]
  PIN rw0_addr_in[0]
    DIRECTION INPUT ;
    USE SIGNAL ;
    SHAPE ABUTMENT ;
    PORT
      LAYER M4 ;
      RECT 0.000 80.148 0.072 80.172 ;
    END
  END rw0_addr_in[0]
  PIN rw0_addr_in[1]
    DIRECTION INPUT ;
    USE SIGNAL ;
    SHAPE ABUTMENT ;
    PORT
      LAYER M4 ;
      RECT 0.000 81.396 0.072 81.420 ;
    END
  END rw0_addr_in[1]
  PIN rw0_addr_in[2]
    DIRECTION INPUT ;
    USE SIGNAL ;
    SHAPE ABUTMENT ;
    PORT
      LAYER M4 ;
      RECT 0.000 82.644 0.072 82.668 ;
    END
  END rw0_addr_in[2]
  PIN rw0_addr_in[3]
    DIRECTION INPUT ;
    USE SIGNAL ;
    SHAPE ABUTMENT ;
    PORT
      LAYER M4 ;
      RECT 0.000 83.892 0.072 83.916 ;
    END
  END rw0_addr_in[3]
  PIN rw0_addr_in[4]
    DIRECTION INPUT ;
    USE SIGNAL ;
    SHAPE ABUTMENT ;
    PORT
      LAYER M4 ;
      RECT 138.248 80.148 138.320 80.172 ;
    END
  END rw0_addr_in[4]
  PIN rw0_addr_in[5]
    DIRECTION INPUT ;
    USE SIGNAL ;
    SHAPE ABUTMENT ;
    PORT
      LAYER M4 ;
      RECT 138.248 81.396 138.320 81.420 ;
    END
  END rw0_addr_in[5]
  PIN rw0_addr_in[6]
    DIRECTION INPUT ;
    USE SIGNAL ;
    SHAPE ABUTMENT ;
    PORT
      LAYER M4 ;
      RECT 138.248 82.644 138.320 82.668 ;
    END
  END rw0_addr_in[6]
  PIN rw0_addr_in[7]
    DIRECTION INPUT ;
    USE SIGNAL ;
    SHAPE ABUTMENT ;
    PORT
      LAYER M4 ;
      RECT 138.248 83.892 138.320 83.916 ;
    END
  END rw0_addr_in[7]
  PIN rw0_we_in
    DIRECTION INPUT ;
    USE SIGNAL ;
    SHAPE ABUTMENT ;
    PORT
      LAYER M3 ;
      RECT 133.839 86.746 133.857 86.800 ;
    END
  END rw0_we_in
  PIN rw0_ce_in
    DIRECTION INPUT ;
    USE SIGNAL ;
    SHAPE ABUTMENT ;
    PORT
      LAYER M3 ;
      RECT 134.883 86.746 134.901 86.800 ;
    END
  END rw0_ce_in
  PIN rw0_clk
    DIRECTION INPUT ;
    USE SIGNAL ;
    SHAPE ABUTMENT ;
    PORT
      LAYER M3 ;
      RECT 135.927 86.746 135.945 86.800 ;
    END
  END rw0_clk
  PIN VSS
    DIRECTION INOUT ;
    USE GROUND ;
    PORT
      LAYER M4 ;
      RECT 0.216 0.240 138.104 0.336 ;
      RECT 0.216 1.008 138.104 1.104 ;
      RECT 0.216 1.776 138.104 1.872 ;
      RECT 0.216 2.544 138.104 2.640 ;
      RECT 0.216 3.312 138.104 3.408 ;
      RECT 0.216 4.080 138.104 4.176 ;
      RECT 0.216 4.848 138.104 4.944 ;
      RECT 0.216 5.616 138.104 5.712 ;
      RECT 0.216 6.384 138.104 6.480 ;
      RECT 0.216 7.152 138.104 7.248 ;
      RECT 0.216 7.920 138.104 8.016 ;
      RECT 0.216 8.688 138.104 8.784 ;
      RECT 0.216 9.456 138.104 9.552 ;
      RECT 0.216 10.224 138.104 10.320 ;
      RECT 0.216 10.992 138.104 11.088 ;
      RECT 0.216 11.760 138.104 11.856 ;
      RECT 0.216 12.528 138.104 12.624 ;
      RECT 0.216 13.296 138.104 13.392 ;
      RECT 0.216 14.064 138.104 14.160 ;
      RECT 0.216 14.832 138.104 14.928 ;
      RECT 0.216 15.600 138.104 15.696 ;
      RECT 0.216 16.368 138.104 16.464 ;
      RECT 0.216 17.136 138.104 17.232 ;
      RECT 0.216 17.904 138.104 18.000 ;
      RECT 0.216 18.672 138.104 18.768 ;
      RECT 0.216 19.440 138.104 19.536 ;
      RECT 0.216 20.208 138.104 20.304 ;
      RECT 0.216 20.976 138.104 21.072 ;
      RECT 0.216 21.744 138.104 21.840 ;
      RECT 0.216 22.512 138.104 22.608 ;
      RECT 0.216 23.280 138.104 23.376 ;
      RECT 0.216 24.048 138.104 24.144 ;
      RECT 0.216 24.816 138.104 24.912 ;
      RECT 0.216 25.584 138.104 25.680 ;
      RECT 0.216 26.352 138.104 26.448 ;
      RECT 0.216 27.120 138.104 27.216 ;
      RECT 0.216 27.888 138.104 27.984 ;
      RECT 0.216 28.656 138.104 28.752 ;
      RECT 0.216 29.424 138.104 29.520 ;
      RECT 0.216 30.192 138.104 30.288 ;
      RECT 0.216 30.960 138.104 31.056 ;
      RECT 0.216 31.728 138.104 31.824 ;
      RECT 0.216 32.496 138.104 32.592 ;
      RECT 0.216 33.264 138.104 33.360 ;
      RECT 0.216 34.032 138.104 34.128 ;
      RECT 0.216 34.800 138.104 34.896 ;
      RECT 0.216 35.568 138.104 35.664 ;
      RECT 0.216 36.336 138.104 36.432 ;
      RECT 0.216 37.104 138.104 37.200 ;
      RECT 0.216 37.872 138.104 37.968 ;
      RECT 0.216 38.640 138.104 38.736 ;
      RECT 0.216 39.408 138.104 39.504 ;
      RECT 0.216 40.176 138.104 40.272 ;
      RECT 0.216 40.944 138.104 41.040 ;
      RECT 0.216 41.712 138.104 41.808 ;
      RECT 0.216 42.480 138.104 42.576 ;
      RECT 0.216 43.248 138.104 43.344 ;
      RECT 0.216 44.016 138.104 44.112 ;
      RECT 0.216 44.784 138.104 44.880 ;
      RECT 0.216 45.552 138.104 45.648 ;
      RECT 0.216 46.320 138.104 46.416 ;
      RECT 0.216 47.088 138.104 47.184 ;
      RECT 0.216 47.856 138.104 47.952 ;
      RECT 0.216 48.624 138.104 48.720 ;
      RECT 0.216 49.392 138.104 49.488 ;
      RECT 0.216 50.160 138.104 50.256 ;
      RECT 0.216 50.928 138.104 51.024 ;
      RECT 0.216 51.696 138.104 51.792 ;
      RECT 0.216 52.464 138.104 52.560 ;
      RECT 0.216 53.232 138.104 53.328 ;
      RECT 0.216 54.000 138.104 54.096 ;
      RECT 0.216 54.768 138.104 54.864 ;
      RECT 0.216 55.536 138.104 55.632 ;
      RECT 0.216 56.304 138.104 56.400 ;
      RECT 0.216 57.072 138.104 57.168 ;
      RECT 0.216 57.840 138.104 57.936 ;
      RECT 0.216 58.608 138.104 58.704 ;
      RECT 0.216 59.376 138.104 59.472 ;
      RECT 0.216 60.144 138.104 60.240 ;
      RECT 0.216 60.912 138.104 61.008 ;
      RECT 0.216 61.680 138.104 61.776 ;
      RECT 0.216 62.448 138.104 62.544 ;
      RECT 0.216 63.216 138.104 63.312 ;
      RECT 0.216 63.984 138.104 64.080 ;
      RECT 0.216 64.752 138.104 64.848 ;
      RECT 0.216 65.520 138.104 65.616 ;
      RECT 0.216 66.288 138.104 66.384 ;
      RECT 0.216 67.056 138.104 67.152 ;
      RECT 0.216 67.824 138.104 67.920 ;
      RECT 0.216 68.592 138.104 68.688 ;
      RECT 0.216 69.360 138.104 69.456 ;
      RECT 0.216 70.128 138.104 70.224 ;
      RECT 0.216 70.896 138.104 70.992 ;
      RECT 0.216 71.664 138.104 71.760 ;
      RECT 0.216 72.432 138.104 72.528 ;
      RECT 0.216 73.200 138.104 73.296 ;
      RECT 0.216 73.968 138.104 74.064 ;
      RECT 0.216 74.736 138.104 74.832 ;
      RECT 0.216 75.504 138.104 75.600 ;
      RECT 0.216 76.272 138.104 76.368 ;
      RECT 0.216 77.040 138.104 77.136 ;
      RECT 0.216 77.808 138.104 77.904 ;
      RECT 0.216 78.576 138.104 78.672 ;
      RECT 0.216 79.344 138.104 79.440 ;
      RECT 0.216 80.112 138.104 80.208 ;
      RECT 0.216 80.880 138.104 80.976 ;
      RECT 0.216 81.648 138.104 81.744 ;
      RECT 0.216 82.416 138.104 82.512 ;
      RECT 0.216 83.184 138.104 83.280 ;
      RECT 0.216 83.952 138.104 84.048 ;
      RECT 0.216 84.720 138.104 84.816 ;
      RECT 0.216 85.488 138.104 85.584 ;
      RECT 0.216 86.256 138.104 86.352 ;
    END
  END VSS
  PIN VDD
    DIRECTION INOUT ;
    USE POWER ;
    PORT
      LAYER M4 ;
      RECT 0.216 0.624 138.104 0.720 ;
      RECT 0.216 1.392 138.104 1.488 ;
      RECT 0.216 2.160 138.104 2.256 ;
      RECT 0.216 2.928 138.104 3.024 ;
      RECT 0.216 3.696 138.104 3.792 ;
      RECT 0.216 4.464 138.104 4.560 ;
      RECT 0.216 5.232 138.104 5.328 ;
      RECT 0.216 6.000 138.104 6.096 ;
      RECT 0.216 6.768 138.104 6.864 ;
      RECT 0.216 7.536 138.104 7.632 ;
      RECT 0.216 8.304 138.104 8.400 ;
      RECT 0.216 9.072 138.104 9.168 ;
      RECT 0.216 9.840 138.104 9.936 ;
      RECT 0.216 10.608 138.104 10.704 ;
      RECT 0.216 11.376 138.104 11.472 ;
      RECT 0.216 12.144 138.104 12.240 ;
      RECT 0.216 12.912 138.104 13.008 ;
      RECT 0.216 13.680 138.104 13.776 ;
      RECT 0.216 14.448 138.104 14.544 ;
      RECT 0.216 15.216 138.104 15.312 ;
      RECT 0.216 15.984 138.104 16.080 ;
      RECT 0.216 16.752 138.104 16.848 ;
      RECT 0.216 17.520 138.104 17.616 ;
      RECT 0.216 18.288 138.104 18.384 ;
      RECT 0.216 19.056 138.104 19.152 ;
      RECT 0.216 19.824 138.104 19.920 ;
      RECT 0.216 20.592 138.104 20.688 ;
      RECT 0.216 21.360 138.104 21.456 ;
      RECT 0.216 22.128 138.104 22.224 ;
      RECT 0.216 22.896 138.104 22.992 ;
      RECT 0.216 23.664 138.104 23.760 ;
      RECT 0.216 24.432 138.104 24.528 ;
      RECT 0.216 25.200 138.104 25.296 ;
      RECT 0.216 25.968 138.104 26.064 ;
      RECT 0.216 26.736 138.104 26.832 ;
      RECT 0.216 27.504 138.104 27.600 ;
      RECT 0.216 28.272 138.104 28.368 ;
      RECT 0.216 29.040 138.104 29.136 ;
      RECT 0.216 29.808 138.104 29.904 ;
      RECT 0.216 30.576 138.104 30.672 ;
      RECT 0.216 31.344 138.104 31.440 ;
      RECT 0.216 32.112 138.104 32.208 ;
      RECT 0.216 32.880 138.104 32.976 ;
      RECT 0.216 33.648 138.104 33.744 ;
      RECT 0.216 34.416 138.104 34.512 ;
      RECT 0.216 35.184 138.104 35.280 ;
      RECT 0.216 35.952 138.104 36.048 ;
      RECT 0.216 36.720 138.104 36.816 ;
      RECT 0.216 37.488 138.104 37.584 ;
      RECT 0.216 38.256 138.104 38.352 ;
      RECT 0.216 39.024 138.104 39.120 ;
      RECT 0.216 39.792 138.104 39.888 ;
      RECT 0.216 40.560 138.104 40.656 ;
      RECT 0.216 41.328 138.104 41.424 ;
      RECT 0.216 42.096 138.104 42.192 ;
      RECT 0.216 42.864 138.104 42.960 ;
      RECT 0.216 43.632 138.104 43.728 ;
      RECT 0.216 44.400 138.104 44.496 ;
      RECT 0.216 45.168 138.104 45.264 ;
      RECT 0.216 45.936 138.104 46.032 ;
      RECT 0.216 46.704 138.104 46.800 ;
      RECT 0.216 47.472 138.104 47.568 ;
      RECT 0.216 48.240 138.104 48.336 ;
      RECT 0.216 49.008 138.104 49.104 ;
      RECT 0.216 49.776 138.104 49.872 ;
      RECT 0.216 50.544 138.104 50.640 ;
      RECT 0.216 51.312 138.104 51.408 ;
      RECT 0.216 52.080 138.104 52.176 ;
      RECT 0.216 52.848 138.104 52.944 ;
      RECT 0.216 53.616 138.104 53.712 ;
      RECT 0.216 54.384 138.104 54.480 ;
      RECT 0.216 55.152 138.104 55.248 ;
      RECT 0.216 55.920 138.104 56.016 ;
      RECT 0.216 56.688 138.104 56.784 ;
      RECT 0.216 57.456 138.104 57.552 ;
      RECT 0.216 58.224 138.104 58.320 ;
      RECT 0.216 58.992 138.104 59.088 ;
      RECT 0.216 59.760 138.104 59.856 ;
      RECT 0.216 60.528 138.104 60.624 ;
      RECT 0.216 61.296 138.104 61.392 ;
      RECT 0.216 62.064 138.104 62.160 ;
      RECT 0.216 62.832 138.104 62.928 ;
      RECT 0.216 63.600 138.104 63.696 ;
      RECT 0.216 64.368 138.104 64.464 ;
      RECT 0.216 65.136 138.104 65.232 ;
      RECT 0.216 65.904 138.104 66.000 ;
      RECT 0.216 66.672 138.104 66.768 ;
      RECT 0.216 67.440 138.104 67.536 ;
      RECT 0.216 68.208 138.104 68.304 ;
      RECT 0.216 68.976 138.104 69.072 ;
      RECT 0.216 69.744 138.104 69.840 ;
      RECT 0.216 70.512 138.104 70.608 ;
      RECT 0.216 71.280 138.104 71.376 ;
      RECT 0.216 72.048 138.104 72.144 ;
      RECT 0.216 72.816 138.104 72.912 ;
      RECT 0.216 73.584 138.104 73.680 ;
      RECT 0.216 74.352 138.104 74.448 ;
      RECT 0.216 75.120 138.104 75.216 ;
      RECT 0.216 75.888 138.104 75.984 ;
      RECT 0.216 76.656 138.104 76.752 ;
      RECT 0.216 77.424 138.104 77.520 ;
      RECT 0.216 78.192 138.104 78.288 ;
      RECT 0.216 78.960 138.104 79.056 ;
      RECT 0.216 79.728 138.104 79.824 ;
      RECT 0.216 80.496 138.104 80.592 ;
      RECT 0.216 81.264 138.104 81.360 ;
      RECT 0.216 82.032 138.104 82.128 ;
      RECT 0.216 82.800 138.104 82.896 ;
      RECT 0.216 83.568 138.104 83.664 ;
      RECT 0.216 84.336 138.104 84.432 ;
      RECT 0.216 85.104 138.104 85.200 ;
      RECT 0.216 85.872 138.104 85.968 ;
      RECT 0.216 86.640 138.104 86.736 ;
    END
  END VDD
  OBS
    LAYER M1 ;
    RECT 0 0 138.320 86.800 ;
    LAYER M2 ;
    RECT 0 0 138.320 86.800 ;
    LAYER M3 ;
    RECT 0 0 138.320 86.800 ;
    LAYER M4 ;
    RECT 0 0 138.320 86.800 ;
  END
END fakeram_256x256

END LIBRARY
